VERSION 5.8 ;
BUSBITCHARS "[]" ;
DIVIDERCHAR "/" ;
UNITS
    DATABASE MICRONS 1000 ;
END UNITS

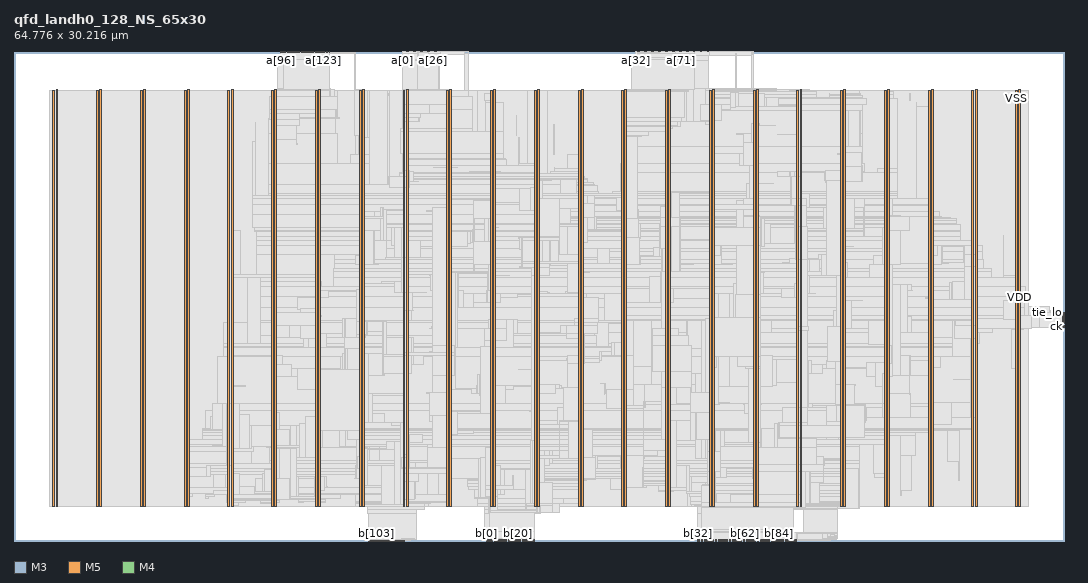
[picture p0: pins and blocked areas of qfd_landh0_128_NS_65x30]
MACRO qfd_landh0_128_NS_65x30
  FOREIGN qfd_landh0_128_NS_65x30 0 0 ;
  CLASS BLOCK ;
  SIZE 64.776 BY 30.216 ;
  PIN a[0]
    DIRECTION INPUT ;
    USE SIGNAL ;
    PORT
      LAYER M3 ;
        RECT  23.94 30.179 23.958 30.216 ;
    END
  END a[0]
  PIN a[100]
    DIRECTION INPUT ;
    USE SIGNAL ;
    PORT
      LAYER M5 ;
        RECT  16.848 30.132 16.872 30.216 ;
    END
  END a[100]
  PIN a[101]
    DIRECTION INPUT ;
    USE SIGNAL ;
    PORT
      LAYER M5 ;
        RECT  16.944 30.132 16.968 30.216 ;
    END
  END a[101]
  PIN a[102]
    DIRECTION INPUT ;
    USE SIGNAL ;
    PORT
      LAYER M5 ;
        RECT  17.04 30.132 17.064 30.216 ;
    END
  END a[102]
  PIN a[103]
    DIRECTION INPUT ;
    USE SIGNAL ;
    PORT
      LAYER M5 ;
        RECT  17.136 30.132 17.16 30.216 ;
    END
  END a[103]
  PIN a[104]
    DIRECTION INPUT ;
    USE SIGNAL ;
    PORT
      LAYER M5 ;
        RECT  17.232 30.132 17.256 30.216 ;
    END
  END a[104]
  PIN a[105]
    DIRECTION INPUT ;
    USE SIGNAL ;
    PORT
      LAYER M5 ;
        RECT  17.328 30.132 17.352 30.216 ;
    END
  END a[105]
  PIN a[106]
    DIRECTION INPUT ;
    USE SIGNAL ;
    PORT
      LAYER M5 ;
        RECT  17.424 30.132 17.448 30.216 ;
    END
  END a[106]
  PIN a[107]
    DIRECTION INPUT ;
    USE SIGNAL ;
    PORT
      LAYER M5 ;
        RECT  17.52 30.132 17.544 30.216 ;
    END
  END a[107]
  PIN a[108]
    DIRECTION INPUT ;
    USE SIGNAL ;
    PORT
      LAYER M5 ;
        RECT  17.616 30.132 17.64 30.216 ;
    END
  END a[108]
  PIN a[109]
    DIRECTION INPUT ;
    USE SIGNAL ;
    PORT
      LAYER M5 ;
        RECT  17.712 30.132 17.736 30.216 ;
    END
  END a[109]
  PIN a[10]
    DIRECTION INPUT ;
    USE SIGNAL ;
    PORT
      LAYER M3 ;
        RECT  24.66 30.179 24.678 30.216 ;
    END
  END a[10]
  PIN a[110]
    DIRECTION INPUT ;
    USE SIGNAL ;
    PORT
      LAYER M5 ;
        RECT  17.808 30.132 17.832 30.216 ;
    END
  END a[110]
  PIN a[111]
    DIRECTION INPUT ;
    USE SIGNAL ;
    PORT
      LAYER M5 ;
        RECT  17.904 30.132 17.928 30.216 ;
    END
  END a[111]
  PIN a[112]
    DIRECTION INPUT ;
    USE SIGNAL ;
    PORT
      LAYER M5 ;
        RECT  18 30.132 18.024 30.216 ;
    END
  END a[112]
  PIN a[113]
    DIRECTION INPUT ;
    USE SIGNAL ;
    PORT
      LAYER M5 ;
        RECT  18.096 30.132 18.12 30.216 ;
    END
  END a[113]
  PIN a[114]
    DIRECTION INPUT ;
    USE SIGNAL ;
    PORT
      LAYER M5 ;
        RECT  18.192 30.132 18.216 30.216 ;
    END
  END a[114]
  PIN a[115]
    DIRECTION INPUT ;
    USE SIGNAL ;
    PORT
      LAYER M5 ;
        RECT  18.288 30.132 18.312 30.216 ;
    END
  END a[115]
  PIN a[116]
    DIRECTION INPUT ;
    USE SIGNAL ;
    PORT
      LAYER M5 ;
        RECT  18.384 30.132 18.408 30.216 ;
    END
  END a[116]
  PIN a[117]
    DIRECTION INPUT ;
    USE SIGNAL ;
    PORT
      LAYER M5 ;
        RECT  18.48 30.132 18.504 30.216 ;
    END
  END a[117]
  PIN a[118]
    DIRECTION INPUT ;
    USE SIGNAL ;
    PORT
      LAYER M5 ;
        RECT  18.576 30.132 18.6 30.216 ;
    END
  END a[118]
  PIN a[119]
    DIRECTION INPUT ;
    USE SIGNAL ;
    PORT
      LAYER M5 ;
        RECT  18.672 30.132 18.696 30.216 ;
    END
  END a[119]
  PIN a[11]
    DIRECTION INPUT ;
    USE SIGNAL ;
    PORT
      LAYER M3 ;
        RECT  24.732 30.179 24.75 30.216 ;
    END
  END a[11]
  PIN a[120]
    DIRECTION INPUT ;
    USE SIGNAL ;
    PORT
      LAYER M5 ;
        RECT  18.768 30.132 18.792 30.216 ;
    END
  END a[120]
  PIN a[121]
    DIRECTION INPUT ;
    USE SIGNAL ;
    PORT
      LAYER M5 ;
        RECT  18.864 30.132 18.888 30.216 ;
    END
  END a[121]
  PIN a[122]
    DIRECTION INPUT ;
    USE SIGNAL ;
    PORT
      LAYER M5 ;
        RECT  18.96 30.132 18.984 30.216 ;
    END
  END a[122]
  PIN a[123]
    DIRECTION INPUT ;
    USE SIGNAL ;
    PORT
      LAYER M5 ;
        RECT  19.056 30.132 19.08 30.216 ;
    END
  END a[123]
  PIN a[124]
    DIRECTION INPUT ;
    USE SIGNAL ;
    PORT
      LAYER M5 ;
        RECT  19.152 30.132 19.176 30.216 ;
    END
  END a[124]
  PIN a[125]
    DIRECTION INPUT ;
    USE SIGNAL ;
    PORT
      LAYER M5 ;
        RECT  19.248 30.132 19.272 30.216 ;
    END
  END a[125]
  PIN a[126]
    DIRECTION INPUT ;
    USE SIGNAL ;
    PORT
      LAYER M5 ;
        RECT  19.344 30.132 19.368 30.216 ;
    END
  END a[126]
  PIN a[127]
    DIRECTION INPUT ;
    USE SIGNAL ;
    PORT
      LAYER M5 ;
        RECT  19.44 30.132 19.464 30.216 ;
    END
  END a[127]
  PIN a[12]
    DIRECTION INPUT ;
    USE SIGNAL ;
    PORT
      LAYER M3 ;
        RECT  24.804 30.179 24.822 30.216 ;
    END
  END a[12]
  PIN a[13]
    DIRECTION INPUT ;
    USE SIGNAL ;
    PORT
      LAYER M3 ;
        RECT  24.876 30.179 24.894 30.216 ;
    END
  END a[13]
  PIN a[14]
    DIRECTION INPUT ;
    USE SIGNAL ;
    PORT
      LAYER M3 ;
        RECT  24.948 30.179 24.966 30.216 ;
    END
  END a[14]
  PIN a[15]
    DIRECTION INPUT ;
    USE SIGNAL ;
    PORT
      LAYER M3 ;
        RECT  25.02 30.179 25.038 30.216 ;
    END
  END a[15]
  PIN a[16]
    DIRECTION INPUT ;
    USE SIGNAL ;
    PORT
      LAYER M3 ;
        RECT  25.092 30.179 25.11 30.216 ;
    END
  END a[16]
  PIN a[17]
    DIRECTION INPUT ;
    USE SIGNAL ;
    PORT
      LAYER M3 ;
        RECT  25.164 30.179 25.182 30.216 ;
    END
  END a[17]
  PIN a[18]
    DIRECTION INPUT ;
    USE SIGNAL ;
    PORT
      LAYER M3 ;
        RECT  25.236 30.179 25.254 30.216 ;
    END
  END a[18]
  PIN a[19]
    DIRECTION INPUT ;
    USE SIGNAL ;
    PORT
      LAYER M3 ;
        RECT  25.308 30.179 25.326 30.216 ;
    END
  END a[19]
  PIN a[1]
    DIRECTION INPUT ;
    USE SIGNAL ;
    PORT
      LAYER M3 ;
        RECT  24.012 30.179 24.03 30.216 ;
    END
  END a[1]
  PIN a[20]
    DIRECTION INPUT ;
    USE SIGNAL ;
    PORT
      LAYER M3 ;
        RECT  25.38 30.179 25.398 30.216 ;
    END
  END a[20]
  PIN a[21]
    DIRECTION INPUT ;
    USE SIGNAL ;
    PORT
      LAYER M3 ;
        RECT  25.452 30.179 25.47 30.216 ;
    END
  END a[21]
  PIN a[22]
    DIRECTION INPUT ;
    USE SIGNAL ;
    PORT
      LAYER M3 ;
        RECT  25.524 30.179 25.542 30.216 ;
    END
  END a[22]
  PIN a[23]
    DIRECTION INPUT ;
    USE SIGNAL ;
    PORT
      LAYER M3 ;
        RECT  25.596 30.179 25.614 30.216 ;
    END
  END a[23]
  PIN a[24]
    DIRECTION INPUT ;
    USE SIGNAL ;
    PORT
      LAYER M3 ;
        RECT  25.668 30.179 25.686 30.216 ;
    END
  END a[24]
  PIN a[25]
    DIRECTION INPUT ;
    USE SIGNAL ;
    PORT
      LAYER M3 ;
        RECT  25.74 30.179 25.758 30.216 ;
    END
  END a[25]
  PIN a[26]
    DIRECTION INPUT ;
    USE SIGNAL ;
    PORT
      LAYER M3 ;
        RECT  25.812 30.179 25.83 30.216 ;
    END
  END a[26]
  PIN a[27]
    DIRECTION INPUT ;
    USE SIGNAL ;
    PORT
      LAYER M3 ;
        RECT  25.884 30.179 25.902 30.216 ;
    END
  END a[27]
  PIN a[28]
    DIRECTION INPUT ;
    USE SIGNAL ;
    PORT
      LAYER M3 ;
        RECT  25.956 30.179 25.974 30.216 ;
    END
  END a[28]
  PIN a[29]
    DIRECTION INPUT ;
    USE SIGNAL ;
    PORT
      LAYER M3 ;
        RECT  26.028 30.179 26.046 30.216 ;
    END
  END a[29]
  PIN a[2]
    DIRECTION INPUT ;
    USE SIGNAL ;
    PORT
      LAYER M3 ;
        RECT  24.084 30.179 24.102 30.216 ;
    END
  END a[2]
  PIN a[30]
    DIRECTION INPUT ;
    USE SIGNAL ;
    PORT
      LAYER M3 ;
        RECT  26.1 30.179 26.118 30.216 ;
    END
  END a[30]
  PIN a[31]
    DIRECTION INPUT ;
    USE SIGNAL ;
    PORT
      LAYER M3 ;
        RECT  26.172 30.179 26.19 30.216 ;
    END
  END a[31]
  PIN a[32]
    DIRECTION INPUT ;
    USE SIGNAL ;
    PORT
      LAYER M3 ;
        RECT  38.34 30.179 38.358 30.216 ;
    END
  END a[32]
  PIN a[33]
    DIRECTION INPUT ;
    USE SIGNAL ;
    PORT
      LAYER M3 ;
        RECT  38.412 30.179 38.43 30.216 ;
    END
  END a[33]
  PIN a[34]
    DIRECTION INPUT ;
    USE SIGNAL ;
    PORT
      LAYER M3 ;
        RECT  38.484 30.179 38.502 30.216 ;
    END
  END a[34]
  PIN a[35]
    DIRECTION INPUT ;
    USE SIGNAL ;
    PORT
      LAYER M3 ;
        RECT  38.556 30.179 38.574 30.216 ;
    END
  END a[35]
  PIN a[36]
    DIRECTION INPUT ;
    USE SIGNAL ;
    PORT
      LAYER M3 ;
        RECT  38.628 30.179 38.646 30.216 ;
    END
  END a[36]
  PIN a[37]
    DIRECTION INPUT ;
    USE SIGNAL ;
    PORT
      LAYER M3 ;
        RECT  38.7 30.179 38.718 30.216 ;
    END
  END a[37]
  PIN a[38]
    DIRECTION INPUT ;
    USE SIGNAL ;
    PORT
      LAYER M3 ;
        RECT  38.772 30.179 38.79 30.216 ;
    END
  END a[38]
  PIN a[39]
    DIRECTION INPUT ;
    USE SIGNAL ;
    PORT
      LAYER M3 ;
        RECT  38.844 30.179 38.862 30.216 ;
    END
  END a[39]
  PIN a[3]
    DIRECTION INPUT ;
    USE SIGNAL ;
    PORT
      LAYER M3 ;
        RECT  24.156 30.179 24.174 30.216 ;
    END
  END a[3]
  PIN a[40]
    DIRECTION INPUT ;
    USE SIGNAL ;
    PORT
      LAYER M3 ;
        RECT  38.916 30.179 38.934 30.216 ;
    END
  END a[40]
  PIN a[41]
    DIRECTION INPUT ;
    USE SIGNAL ;
    PORT
      LAYER M3 ;
        RECT  38.988 30.179 39.006 30.216 ;
    END
  END a[41]
  PIN a[42]
    DIRECTION INPUT ;
    USE SIGNAL ;
    PORT
      LAYER M3 ;
        RECT  39.06 30.179 39.078 30.216 ;
    END
  END a[42]
  PIN a[43]
    DIRECTION INPUT ;
    USE SIGNAL ;
    PORT
      LAYER M3 ;
        RECT  39.132 30.179 39.15 30.216 ;
    END
  END a[43]
  PIN a[44]
    DIRECTION INPUT ;
    USE SIGNAL ;
    PORT
      LAYER M3 ;
        RECT  39.204 30.179 39.222 30.216 ;
    END
  END a[44]
  PIN a[45]
    DIRECTION INPUT ;
    USE SIGNAL ;
    PORT
      LAYER M3 ;
        RECT  39.276 30.179 39.294 30.216 ;
    END
  END a[45]
  PIN a[46]
    DIRECTION INPUT ;
    USE SIGNAL ;
    PORT
      LAYER M3 ;
        RECT  39.348 30.179 39.366 30.216 ;
    END
  END a[46]
  PIN a[47]
    DIRECTION INPUT ;
    USE SIGNAL ;
    PORT
      LAYER M3 ;
        RECT  39.42 30.179 39.438 30.216 ;
    END
  END a[47]
  PIN a[48]
    DIRECTION INPUT ;
    USE SIGNAL ;
    PORT
      LAYER M3 ;
        RECT  39.492 30.179 39.51 30.216 ;
    END
  END a[48]
  PIN a[49]
    DIRECTION INPUT ;
    USE SIGNAL ;
    PORT
      LAYER M3 ;
        RECT  39.564 30.179 39.582 30.216 ;
    END
  END a[49]
  PIN a[4]
    DIRECTION INPUT ;
    USE SIGNAL ;
    PORT
      LAYER M3 ;
        RECT  24.228 30.179 24.246 30.216 ;
    END
  END a[4]
  PIN a[50]
    DIRECTION INPUT ;
    USE SIGNAL ;
    PORT
      LAYER M3 ;
        RECT  39.636 30.179 39.654 30.216 ;
    END
  END a[50]
  PIN a[51]
    DIRECTION INPUT ;
    USE SIGNAL ;
    PORT
      LAYER M3 ;
        RECT  39.708 30.179 39.726 30.216 ;
    END
  END a[51]
  PIN a[52]
    DIRECTION INPUT ;
    USE SIGNAL ;
    PORT
      LAYER M3 ;
        RECT  39.78 30.179 39.798 30.216 ;
    END
  END a[52]
  PIN a[53]
    DIRECTION INPUT ;
    USE SIGNAL ;
    PORT
      LAYER M3 ;
        RECT  39.852 30.179 39.87 30.216 ;
    END
  END a[53]
  PIN a[54]
    DIRECTION INPUT ;
    USE SIGNAL ;
    PORT
      LAYER M3 ;
        RECT  39.924 30.179 39.942 30.216 ;
    END
  END a[54]
  PIN a[55]
    DIRECTION INPUT ;
    USE SIGNAL ;
    PORT
      LAYER M3 ;
        RECT  39.996 30.179 40.014 30.216 ;
    END
  END a[55]
  PIN a[56]
    DIRECTION INPUT ;
    USE SIGNAL ;
    PORT
      LAYER M3 ;
        RECT  40.068 30.179 40.086 30.216 ;
    END
  END a[56]
  PIN a[57]
    DIRECTION INPUT ;
    USE SIGNAL ;
    PORT
      LAYER M3 ;
        RECT  40.14 30.179 40.158 30.216 ;
    END
  END a[57]
  PIN a[58]
    DIRECTION INPUT ;
    USE SIGNAL ;
    PORT
      LAYER M3 ;
        RECT  40.212 30.179 40.23 30.216 ;
    END
  END a[58]
  PIN a[59]
    DIRECTION INPUT ;
    USE SIGNAL ;
    PORT
      LAYER M3 ;
        RECT  40.284 30.179 40.302 30.216 ;
    END
  END a[59]
  PIN a[5]
    DIRECTION INPUT ;
    USE SIGNAL ;
    PORT
      LAYER M3 ;
        RECT  24.3 30.179 24.318 30.216 ;
    END
  END a[5]
  PIN a[60]
    DIRECTION INPUT ;
    USE SIGNAL ;
    PORT
      LAYER M3 ;
        RECT  40.356 30.179 40.374 30.216 ;
    END
  END a[60]
  PIN a[61]
    DIRECTION INPUT ;
    USE SIGNAL ;
    PORT
      LAYER M3 ;
        RECT  40.428 30.179 40.446 30.216 ;
    END
  END a[61]
  PIN a[62]
    DIRECTION INPUT ;
    USE SIGNAL ;
    PORT
      LAYER M3 ;
        RECT  40.5 30.179 40.518 30.216 ;
    END
  END a[62]
  PIN a[63]
    DIRECTION INPUT ;
    USE SIGNAL ;
    PORT
      LAYER M3 ;
        RECT  40.572 30.179 40.59 30.216 ;
    END
  END a[63]
  PIN a[64]
    DIRECTION INPUT ;
    USE SIGNAL ;
    PORT
      LAYER M3 ;
        RECT  40.644 30.179 40.662 30.216 ;
    END
  END a[64]
  PIN a[65]
    DIRECTION INPUT ;
    USE SIGNAL ;
    PORT
      LAYER M3 ;
        RECT  40.716 30.179 40.734 30.216 ;
    END
  END a[65]
  PIN a[66]
    DIRECTION INPUT ;
    USE SIGNAL ;
    PORT
      LAYER M3 ;
        RECT  40.788 30.179 40.806 30.216 ;
    END
  END a[66]
  PIN a[67]
    DIRECTION INPUT ;
    USE SIGNAL ;
    PORT
      LAYER M3 ;
        RECT  40.86 30.179 40.878 30.216 ;
    END
  END a[67]
  PIN a[68]
    DIRECTION INPUT ;
    USE SIGNAL ;
    PORT
      LAYER M3 ;
        RECT  40.932 30.179 40.95 30.216 ;
    END
  END a[68]
  PIN a[69]
    DIRECTION INPUT ;
    USE SIGNAL ;
    PORT
      LAYER M3 ;
        RECT  41.004 30.179 41.022 30.216 ;
    END
  END a[69]
  PIN a[6]
    DIRECTION INPUT ;
    USE SIGNAL ;
    PORT
      LAYER M3 ;
        RECT  24.372 30.179 24.39 30.216 ;
    END
  END a[6]
  PIN a[70]
    DIRECTION INPUT ;
    USE SIGNAL ;
    PORT
      LAYER M3 ;
        RECT  41.076 30.179 41.094 30.216 ;
    END
  END a[70]
  PIN a[71]
    DIRECTION INPUT ;
    USE SIGNAL ;
    PORT
      LAYER M3 ;
        RECT  41.148 30.179 41.166 30.216 ;
    END
  END a[71]
  PIN a[72]
    DIRECTION INPUT ;
    USE SIGNAL ;
    PORT
      LAYER M3 ;
        RECT  41.22 30.179 41.238 30.216 ;
    END
  END a[72]
  PIN a[73]
    DIRECTION INPUT ;
    USE SIGNAL ;
    PORT
      LAYER M3 ;
        RECT  41.292 30.179 41.31 30.216 ;
    END
  END a[73]
  PIN a[74]
    DIRECTION INPUT ;
    USE SIGNAL ;
    PORT
      LAYER M3 ;
        RECT  41.364 30.179 41.382 30.216 ;
    END
  END a[74]
  PIN a[75]
    DIRECTION INPUT ;
    USE SIGNAL ;
    PORT
      LAYER M3 ;
        RECT  41.436 30.179 41.454 30.216 ;
    END
  END a[75]
  PIN a[76]
    DIRECTION INPUT ;
    USE SIGNAL ;
    PORT
      LAYER M3 ;
        RECT  41.508 30.179 41.526 30.216 ;
    END
  END a[76]
  PIN a[77]
    DIRECTION INPUT ;
    USE SIGNAL ;
    PORT
      LAYER M3 ;
        RECT  41.58 30.179 41.598 30.216 ;
    END
  END a[77]
  PIN a[78]
    DIRECTION INPUT ;
    USE SIGNAL ;
    PORT
      LAYER M3 ;
        RECT  41.652 30.179 41.67 30.216 ;
    END
  END a[78]
  PIN a[79]
    DIRECTION INPUT ;
    USE SIGNAL ;
    PORT
      LAYER M3 ;
        RECT  41.724 30.179 41.742 30.216 ;
    END
  END a[79]
  PIN a[7]
    DIRECTION INPUT ;
    USE SIGNAL ;
    PORT
      LAYER M3 ;
        RECT  24.444 30.179 24.462 30.216 ;
    END
  END a[7]
  PIN a[80]
    DIRECTION INPUT ;
    USE SIGNAL ;
    PORT
      LAYER M3 ;
        RECT  41.796 30.179 41.814 30.216 ;
    END
  END a[80]
  PIN a[81]
    DIRECTION INPUT ;
    USE SIGNAL ;
    PORT
      LAYER M3 ;
        RECT  41.868 30.179 41.886 30.216 ;
    END
  END a[81]
  PIN a[82]
    DIRECTION INPUT ;
    USE SIGNAL ;
    PORT
      LAYER M3 ;
        RECT  41.94 30.179 41.958 30.216 ;
    END
  END a[82]
  PIN a[83]
    DIRECTION INPUT ;
    USE SIGNAL ;
    PORT
      LAYER M3 ;
        RECT  42.012 30.179 42.03 30.216 ;
    END
  END a[83]
  PIN a[84]
    DIRECTION INPUT ;
    USE SIGNAL ;
    PORT
      LAYER M3 ;
        RECT  42.084 30.179 42.102 30.216 ;
    END
  END a[84]
  PIN a[85]
    DIRECTION INPUT ;
    USE SIGNAL ;
    PORT
      LAYER M3 ;
        RECT  42.156 30.179 42.174 30.216 ;
    END
  END a[85]
  PIN a[86]
    DIRECTION INPUT ;
    USE SIGNAL ;
    PORT
      LAYER M3 ;
        RECT  42.228 30.179 42.246 30.216 ;
    END
  END a[86]
  PIN a[87]
    DIRECTION INPUT ;
    USE SIGNAL ;
    PORT
      LAYER M3 ;
        RECT  42.3 30.179 42.318 30.216 ;
    END
  END a[87]
  PIN a[88]
    DIRECTION INPUT ;
    USE SIGNAL ;
    PORT
      LAYER M3 ;
        RECT  42.372 30.179 42.39 30.216 ;
    END
  END a[88]
  PIN a[89]
    DIRECTION INPUT ;
    USE SIGNAL ;
    PORT
      LAYER M3 ;
        RECT  42.444 30.179 42.462 30.216 ;
    END
  END a[89]
  PIN a[8]
    DIRECTION INPUT ;
    USE SIGNAL ;
    PORT
      LAYER M3 ;
        RECT  24.516 30.179 24.534 30.216 ;
    END
  END a[8]
  PIN a[90]
    DIRECTION INPUT ;
    USE SIGNAL ;
    PORT
      LAYER M3 ;
        RECT  42.516 30.179 42.534 30.216 ;
    END
  END a[90]
  PIN a[91]
    DIRECTION INPUT ;
    USE SIGNAL ;
    PORT
      LAYER M3 ;
        RECT  42.588 30.179 42.606 30.216 ;
    END
  END a[91]
  PIN a[92]
    DIRECTION INPUT ;
    USE SIGNAL ;
    PORT
      LAYER M3 ;
        RECT  42.66 30.179 42.678 30.216 ;
    END
  END a[92]
  PIN a[93]
    DIRECTION INPUT ;
    USE SIGNAL ;
    PORT
      LAYER M3 ;
        RECT  42.732 30.179 42.75 30.216 ;
    END
  END a[93]
  PIN a[94]
    DIRECTION INPUT ;
    USE SIGNAL ;
    PORT
      LAYER M3 ;
        RECT  42.804 30.179 42.822 30.216 ;
    END
  END a[94]
  PIN a[95]
    DIRECTION INPUT ;
    USE SIGNAL ;
    PORT
      LAYER M3 ;
        RECT  42.876 30.179 42.894 30.216 ;
    END
  END a[95]
  PIN a[96]
    DIRECTION INPUT ;
    USE SIGNAL ;
    PORT
      LAYER M5 ;
        RECT  16.464 30.132 16.488 30.216 ;
    END
  END a[96]
  PIN a[97]
    DIRECTION INPUT ;
    USE SIGNAL ;
    PORT
      LAYER M5 ;
        RECT  16.56 30.132 16.584 30.216 ;
    END
  END a[97]
  PIN a[98]
    DIRECTION INPUT ;
    USE SIGNAL ;
    PORT
      LAYER M5 ;
        RECT  16.656 30.132 16.68 30.216 ;
    END
  END a[98]
  PIN a[99]
    DIRECTION INPUT ;
    USE SIGNAL ;
    PORT
      LAYER M5 ;
        RECT  16.752 30.132 16.776 30.216 ;
    END
  END a[99]
  PIN a[9]
    DIRECTION INPUT ;
    USE SIGNAL ;
    PORT
      LAYER M3 ;
        RECT  24.588 30.179 24.606 30.216 ;
    END
  END a[9]
  PIN b[0]
    DIRECTION OUTPUT ;
    USE SIGNAL ;
    PORT
      LAYER M5 ;
        RECT  29.136 0 29.16 0.084 ;
    END
  END b[0]
  PIN b[100]
    DIRECTION OUTPUT ;
    USE SIGNAL ;
    PORT
      LAYER M3 ;
        RECT  22.14 0 22.158 0.037 ;
    END
  END b[100]
  PIN b[101]
    DIRECTION OUTPUT ;
    USE SIGNAL ;
    PORT
      LAYER M3 ;
        RECT  22.212 0 22.23 0.037 ;
    END
  END b[101]
  PIN b[102]
    DIRECTION OUTPUT ;
    USE SIGNAL ;
    PORT
      LAYER M3 ;
        RECT  22.284 0 22.302 0.037 ;
    END
  END b[102]
  PIN b[103]
    DIRECTION OUTPUT ;
    USE SIGNAL ;
    PORT
      LAYER M3 ;
        RECT  22.356 0 22.374 0.037 ;
    END
  END b[103]
  PIN b[104]
    DIRECTION OUTPUT ;
    USE SIGNAL ;
    PORT
      LAYER M3 ;
        RECT  22.428 0 22.446 0.037 ;
    END
  END b[104]
  PIN b[105]
    DIRECTION OUTPUT ;
    USE SIGNAL ;
    PORT
      LAYER M3 ;
        RECT  22.5 0 22.518 0.037 ;
    END
  END b[105]
  PIN b[106]
    DIRECTION OUTPUT ;
    USE SIGNAL ;
    PORT
      LAYER M3 ;
        RECT  22.572 0 22.59 0.037 ;
    END
  END b[106]
  PIN b[107]
    DIRECTION OUTPUT ;
    USE SIGNAL ;
    PORT
      LAYER M3 ;
        RECT  22.644 0 22.662 0.037 ;
    END
  END b[107]
  PIN b[108]
    DIRECTION OUTPUT ;
    USE SIGNAL ;
    PORT
      LAYER M3 ;
        RECT  22.716 0 22.734 0.037 ;
    END
  END b[108]
  PIN b[109]
    DIRECTION OUTPUT ;
    USE SIGNAL ;
    PORT
      LAYER M3 ;
        RECT  22.788 0 22.806 0.037 ;
    END
  END b[109]
  PIN b[10]
    DIRECTION OUTPUT ;
    USE SIGNAL ;
    PORT
      LAYER M5 ;
        RECT  30.096 0 30.12 0.084 ;
    END
  END b[10]
  PIN b[110]
    DIRECTION OUTPUT ;
    USE SIGNAL ;
    PORT
      LAYER M3 ;
        RECT  22.86 0 22.878 0.037 ;
    END
  END b[110]
  PIN b[111]
    DIRECTION OUTPUT ;
    USE SIGNAL ;
    PORT
      LAYER M3 ;
        RECT  22.932 0 22.95 0.037 ;
    END
  END b[111]
  PIN b[112]
    DIRECTION OUTPUT ;
    USE SIGNAL ;
    PORT
      LAYER M3 ;
        RECT  23.004 0 23.022 0.037 ;
    END
  END b[112]
  PIN b[113]
    DIRECTION OUTPUT ;
    USE SIGNAL ;
    PORT
      LAYER M3 ;
        RECT  23.076 0 23.094 0.037 ;
    END
  END b[113]
  PIN b[114]
    DIRECTION OUTPUT ;
    USE SIGNAL ;
    PORT
      LAYER M3 ;
        RECT  23.148 0 23.166 0.037 ;
    END
  END b[114]
  PIN b[115]
    DIRECTION OUTPUT ;
    USE SIGNAL ;
    PORT
      LAYER M3 ;
        RECT  23.22 0 23.238 0.037 ;
    END
  END b[115]
  PIN b[116]
    DIRECTION OUTPUT ;
    USE SIGNAL ;
    PORT
      LAYER M3 ;
        RECT  23.292 0 23.31 0.037 ;
    END
  END b[116]
  PIN b[117]
    DIRECTION OUTPUT ;
    USE SIGNAL ;
    PORT
      LAYER M3 ;
        RECT  23.364 0 23.382 0.037 ;
    END
  END b[117]
  PIN b[118]
    DIRECTION OUTPUT ;
    USE SIGNAL ;
    PORT
      LAYER M3 ;
        RECT  23.436 0 23.454 0.037 ;
    END
  END b[118]
  PIN b[119]
    DIRECTION OUTPUT ;
    USE SIGNAL ;
    PORT
      LAYER M3 ;
        RECT  23.508 0 23.526 0.037 ;
    END
  END b[119]
  PIN b[11]
    DIRECTION OUTPUT ;
    USE SIGNAL ;
    PORT
      LAYER M5 ;
        RECT  30.192 0 30.216 0.084 ;
    END
  END b[11]
  PIN b[120]
    DIRECTION OUTPUT ;
    USE SIGNAL ;
    PORT
      LAYER M3 ;
        RECT  23.58 0 23.598 0.037 ;
    END
  END b[120]
  PIN b[121]
    DIRECTION OUTPUT ;
    USE SIGNAL ;
    PORT
      LAYER M3 ;
        RECT  23.652 0 23.67 0.037 ;
    END
  END b[121]
  PIN b[122]
    DIRECTION OUTPUT ;
    USE SIGNAL ;
    PORT
      LAYER M3 ;
        RECT  23.724 0 23.742 0.037 ;
    END
  END b[122]
  PIN b[123]
    DIRECTION OUTPUT ;
    USE SIGNAL ;
    PORT
      LAYER M3 ;
        RECT  23.796 0 23.814 0.037 ;
    END
  END b[123]
  PIN b[124]
    DIRECTION OUTPUT ;
    USE SIGNAL ;
    PORT
      LAYER M3 ;
        RECT  23.868 0 23.886 0.037 ;
    END
  END b[124]
  PIN b[125]
    DIRECTION OUTPUT ;
    USE SIGNAL ;
    PORT
      LAYER M3 ;
        RECT  23.94 0 23.958 0.037 ;
    END
  END b[125]
  PIN b[126]
    DIRECTION OUTPUT ;
    USE SIGNAL ;
    PORT
      LAYER M3 ;
        RECT  24.012 0 24.03 0.037 ;
    END
  END b[126]
  PIN b[127]
    DIRECTION OUTPUT ;
    USE SIGNAL ;
    PORT
      LAYER M3 ;
        RECT  24.084 0 24.102 0.037 ;
    END
  END b[127]
  PIN b[12]
    DIRECTION OUTPUT ;
    USE SIGNAL ;
    PORT
      LAYER M5 ;
        RECT  30.288 0 30.312 0.084 ;
    END
  END b[12]
  PIN b[13]
    DIRECTION OUTPUT ;
    USE SIGNAL ;
    PORT
      LAYER M5 ;
        RECT  30.384 0 30.408 0.084 ;
    END
  END b[13]
  PIN b[14]
    DIRECTION OUTPUT ;
    USE SIGNAL ;
    PORT
      LAYER M5 ;
        RECT  30.48 0 30.504 0.084 ;
    END
  END b[14]
  PIN b[15]
    DIRECTION OUTPUT ;
    USE SIGNAL ;
    PORT
      LAYER M5 ;
        RECT  30.576 0 30.6 0.084 ;
    END
  END b[15]
  PIN b[16]
    DIRECTION OUTPUT ;
    USE SIGNAL ;
    PORT
      LAYER M5 ;
        RECT  30.672 0 30.696 0.084 ;
    END
  END b[16]
  PIN b[17]
    DIRECTION OUTPUT ;
    USE SIGNAL ;
    PORT
      LAYER M5 ;
        RECT  30.768 0 30.792 0.084 ;
    END
  END b[17]
  PIN b[18]
    DIRECTION OUTPUT ;
    USE SIGNAL ;
    PORT
      LAYER M5 ;
        RECT  30.864 0 30.888 0.084 ;
    END
  END b[18]
  PIN b[19]
    DIRECTION OUTPUT ;
    USE SIGNAL ;
    PORT
      LAYER M5 ;
        RECT  30.96 0 30.984 0.084 ;
    END
  END b[19]
  PIN b[1]
    DIRECTION OUTPUT ;
    USE SIGNAL ;
    PORT
      LAYER M5 ;
        RECT  29.232 0 29.256 0.084 ;
    END
  END b[1]
  PIN b[20]
    DIRECTION OUTPUT ;
    USE SIGNAL ;
    PORT
      LAYER M5 ;
        RECT  31.056 0 31.08 0.084 ;
    END
  END b[20]
  PIN b[21]
    DIRECTION OUTPUT ;
    USE SIGNAL ;
    PORT
      LAYER M5 ;
        RECT  31.152 0 31.176 0.084 ;
    END
  END b[21]
  PIN b[22]
    DIRECTION OUTPUT ;
    USE SIGNAL ;
    PORT
      LAYER M5 ;
        RECT  31.248 0 31.272 0.084 ;
    END
  END b[22]
  PIN b[23]
    DIRECTION OUTPUT ;
    USE SIGNAL ;
    PORT
      LAYER M5 ;
        RECT  31.344 0 31.368 0.084 ;
    END
  END b[23]
  PIN b[24]
    DIRECTION OUTPUT ;
    USE SIGNAL ;
    PORT
      LAYER M5 ;
        RECT  31.44 0 31.464 0.084 ;
    END
  END b[24]
  PIN b[25]
    DIRECTION OUTPUT ;
    USE SIGNAL ;
    PORT
      LAYER M5 ;
        RECT  31.536 0 31.56 0.084 ;
    END
  END b[25]
  PIN b[26]
    DIRECTION OUTPUT ;
    USE SIGNAL ;
    PORT
      LAYER M5 ;
        RECT  31.632 0 31.656 0.084 ;
    END
  END b[26]
  PIN b[27]
    DIRECTION OUTPUT ;
    USE SIGNAL ;
    PORT
      LAYER M5 ;
        RECT  31.728 0 31.752 0.084 ;
    END
  END b[27]
  PIN b[28]
    DIRECTION OUTPUT ;
    USE SIGNAL ;
    PORT
      LAYER M5 ;
        RECT  31.824 0 31.848 0.084 ;
    END
  END b[28]
  PIN b[29]
    DIRECTION OUTPUT ;
    USE SIGNAL ;
    PORT
      LAYER M5 ;
        RECT  31.92 0 31.944 0.084 ;
    END
  END b[29]
  PIN b[2]
    DIRECTION OUTPUT ;
    USE SIGNAL ;
    PORT
      LAYER M5 ;
        RECT  29.328 0 29.352 0.084 ;
    END
  END b[2]
  PIN b[30]
    DIRECTION OUTPUT ;
    USE SIGNAL ;
    PORT
      LAYER M5 ;
        RECT  32.016 0 32.04 0.084 ;
    END
  END b[30]
  PIN b[31]
    DIRECTION OUTPUT ;
    USE SIGNAL ;
    PORT
      LAYER M5 ;
        RECT  32.112 0 32.136 0.084 ;
    END
  END b[31]
  PIN b[32]
    DIRECTION OUTPUT ;
    USE SIGNAL ;
    PORT
      LAYER M5 ;
        RECT  42.192 0 42.216 0.084 ;
    END
  END b[32]
  PIN b[33]
    DIRECTION OUTPUT ;
    USE SIGNAL ;
    PORT
      LAYER M5 ;
        RECT  42.288 0 42.312 0.084 ;
    END
  END b[33]
  PIN b[34]
    DIRECTION OUTPUT ;
    USE SIGNAL ;
    PORT
      LAYER M5 ;
        RECT  42.384 0 42.408 0.084 ;
    END
  END b[34]
  PIN b[35]
    DIRECTION OUTPUT ;
    USE SIGNAL ;
    PORT
      LAYER M5 ;
        RECT  42.48 0 42.504 0.084 ;
    END
  END b[35]
  PIN b[36]
    DIRECTION OUTPUT ;
    USE SIGNAL ;
    PORT
      LAYER M5 ;
        RECT  42.576 0 42.6 0.084 ;
    END
  END b[36]
  PIN b[37]
    DIRECTION OUTPUT ;
    USE SIGNAL ;
    PORT
      LAYER M5 ;
        RECT  42.672 0 42.696 0.084 ;
    END
  END b[37]
  PIN b[38]
    DIRECTION OUTPUT ;
    USE SIGNAL ;
    PORT
      LAYER M5 ;
        RECT  42.768 0 42.792 0.084 ;
    END
  END b[38]
  PIN b[39]
    DIRECTION OUTPUT ;
    USE SIGNAL ;
    PORT
      LAYER M5 ;
        RECT  42.864 0 42.888 0.084 ;
    END
  END b[39]
  PIN b[3]
    DIRECTION OUTPUT ;
    USE SIGNAL ;
    PORT
      LAYER M5 ;
        RECT  29.424 0 29.448 0.084 ;
    END
  END b[3]
  PIN b[40]
    DIRECTION OUTPUT ;
    USE SIGNAL ;
    PORT
      LAYER M5 ;
        RECT  42.96 0 42.984 0.084 ;
    END
  END b[40]
  PIN b[41]
    DIRECTION OUTPUT ;
    USE SIGNAL ;
    PORT
      LAYER M5 ;
        RECT  43.056 0 43.08 0.084 ;
    END
  END b[41]
  PIN b[42]
    DIRECTION OUTPUT ;
    USE SIGNAL ;
    PORT
      LAYER M5 ;
        RECT  43.152 0 43.176 0.084 ;
    END
  END b[42]
  PIN b[43]
    DIRECTION OUTPUT ;
    USE SIGNAL ;
    PORT
      LAYER M5 ;
        RECT  43.248 0 43.272 0.084 ;
    END
  END b[43]
  PIN b[44]
    DIRECTION OUTPUT ;
    USE SIGNAL ;
    PORT
      LAYER M5 ;
        RECT  43.344 0 43.368 0.084 ;
    END
  END b[44]
  PIN b[45]
    DIRECTION OUTPUT ;
    USE SIGNAL ;
    PORT
      LAYER M5 ;
        RECT  43.44 0 43.464 0.084 ;
    END
  END b[45]
  PIN b[46]
    DIRECTION OUTPUT ;
    USE SIGNAL ;
    PORT
      LAYER M5 ;
        RECT  43.536 0 43.56 0.084 ;
    END
  END b[46]
  PIN b[47]
    DIRECTION OUTPUT ;
    USE SIGNAL ;
    PORT
      LAYER M5 ;
        RECT  43.632 0 43.656 0.084 ;
    END
  END b[47]
  PIN b[48]
    DIRECTION OUTPUT ;
    USE SIGNAL ;
    PORT
      LAYER M5 ;
        RECT  43.728 0 43.752 0.084 ;
    END
  END b[48]
  PIN b[49]
    DIRECTION OUTPUT ;
    USE SIGNAL ;
    PORT
      LAYER M5 ;
        RECT  43.824 0 43.848 0.084 ;
    END
  END b[49]
  PIN b[4]
    DIRECTION OUTPUT ;
    USE SIGNAL ;
    PORT
      LAYER M5 ;
        RECT  29.52 0 29.544 0.084 ;
    END
  END b[4]
  PIN b[50]
    DIRECTION OUTPUT ;
    USE SIGNAL ;
    PORT
      LAYER M5 ;
        RECT  43.92 0 43.944 0.084 ;
    END
  END b[50]
  PIN b[51]
    DIRECTION OUTPUT ;
    USE SIGNAL ;
    PORT
      LAYER M5 ;
        RECT  44.016 0 44.04 0.084 ;
    END
  END b[51]
  PIN b[52]
    DIRECTION OUTPUT ;
    USE SIGNAL ;
    PORT
      LAYER M5 ;
        RECT  44.112 0 44.136 0.084 ;
    END
  END b[52]
  PIN b[53]
    DIRECTION OUTPUT ;
    USE SIGNAL ;
    PORT
      LAYER M5 ;
        RECT  44.208 0 44.232 0.084 ;
    END
  END b[53]
  PIN b[54]
    DIRECTION OUTPUT ;
    USE SIGNAL ;
    PORT
      LAYER M5 ;
        RECT  44.304 0 44.328 0.084 ;
    END
  END b[54]
  PIN b[55]
    DIRECTION OUTPUT ;
    USE SIGNAL ;
    PORT
      LAYER M5 ;
        RECT  44.4 0 44.424 0.084 ;
    END
  END b[55]
  PIN b[56]
    DIRECTION OUTPUT ;
    USE SIGNAL ;
    PORT
      LAYER M5 ;
        RECT  44.496 0 44.52 0.084 ;
    END
  END b[56]
  PIN b[57]
    DIRECTION OUTPUT ;
    USE SIGNAL ;
    PORT
      LAYER M5 ;
        RECT  44.592 0 44.616 0.084 ;
    END
  END b[57]
  PIN b[58]
    DIRECTION OUTPUT ;
    USE SIGNAL ;
    PORT
      LAYER M5 ;
        RECT  44.688 0 44.712 0.084 ;
    END
  END b[58]
  PIN b[59]
    DIRECTION OUTPUT ;
    USE SIGNAL ;
    PORT
      LAYER M5 ;
        RECT  44.784 0 44.808 0.084 ;
    END
  END b[59]
  PIN b[5]
    DIRECTION OUTPUT ;
    USE SIGNAL ;
    PORT
      LAYER M5 ;
        RECT  29.616 0 29.64 0.084 ;
    END
  END b[5]
  PIN b[60]
    DIRECTION OUTPUT ;
    USE SIGNAL ;
    PORT
      LAYER M5 ;
        RECT  44.88 0 44.904 0.084 ;
    END
  END b[60]
  PIN b[61]
    DIRECTION OUTPUT ;
    USE SIGNAL ;
    PORT
      LAYER M5 ;
        RECT  44.976 0 45 0.084 ;
    END
  END b[61]
  PIN b[62]
    DIRECTION OUTPUT ;
    USE SIGNAL ;
    PORT
      LAYER M5 ;
        RECT  45.072 0 45.096 0.084 ;
    END
  END b[62]
  PIN b[63]
    DIRECTION OUTPUT ;
    USE SIGNAL ;
    PORT
      LAYER M5 ;
        RECT  45.168 0 45.192 0.084 ;
    END
  END b[63]
  PIN b[64]
    DIRECTION OUTPUT ;
    USE SIGNAL ;
    PORT
      LAYER M5 ;
        RECT  45.264 0 45.288 0.084 ;
    END
  END b[64]
  PIN b[65]
    DIRECTION OUTPUT ;
    USE SIGNAL ;
    PORT
      LAYER M5 ;
        RECT  45.36 0 45.384 0.084 ;
    END
  END b[65]
  PIN b[66]
    DIRECTION OUTPUT ;
    USE SIGNAL ;
    PORT
      LAYER M5 ;
        RECT  45.456 0 45.48 0.084 ;
    END
  END b[66]
  PIN b[67]
    DIRECTION OUTPUT ;
    USE SIGNAL ;
    PORT
      LAYER M5 ;
        RECT  45.552 0 45.576 0.084 ;
    END
  END b[67]
  PIN b[68]
    DIRECTION OUTPUT ;
    USE SIGNAL ;
    PORT
      LAYER M5 ;
        RECT  45.648 0 45.672 0.084 ;
    END
  END b[68]
  PIN b[69]
    DIRECTION OUTPUT ;
    USE SIGNAL ;
    PORT
      LAYER M5 ;
        RECT  45.744 0 45.768 0.084 ;
    END
  END b[69]
  PIN b[6]
    DIRECTION OUTPUT ;
    USE SIGNAL ;
    PORT
      LAYER M5 ;
        RECT  29.712 0 29.736 0.084 ;
    END
  END b[6]
  PIN b[70]
    DIRECTION OUTPUT ;
    USE SIGNAL ;
    PORT
      LAYER M5 ;
        RECT  45.84 0 45.864 0.084 ;
    END
  END b[70]
  PIN b[71]
    DIRECTION OUTPUT ;
    USE SIGNAL ;
    PORT
      LAYER M5 ;
        RECT  45.936 0 45.96 0.084 ;
    END
  END b[71]
  PIN b[72]
    DIRECTION OUTPUT ;
    USE SIGNAL ;
    PORT
      LAYER M5 ;
        RECT  46.032 0 46.056 0.084 ;
    END
  END b[72]
  PIN b[73]
    DIRECTION OUTPUT ;
    USE SIGNAL ;
    PORT
      LAYER M5 ;
        RECT  46.128 0 46.152 0.084 ;
    END
  END b[73]
  PIN b[74]
    DIRECTION OUTPUT ;
    USE SIGNAL ;
    PORT
      LAYER M5 ;
        RECT  46.224 0 46.248 0.084 ;
    END
  END b[74]
  PIN b[75]
    DIRECTION OUTPUT ;
    USE SIGNAL ;
    PORT
      LAYER M5 ;
        RECT  46.32 0 46.344 0.084 ;
    END
  END b[75]
  PIN b[76]
    DIRECTION OUTPUT ;
    USE SIGNAL ;
    PORT
      LAYER M5 ;
        RECT  46.416 0 46.44 0.084 ;
    END
  END b[76]
  PIN b[77]
    DIRECTION OUTPUT ;
    USE SIGNAL ;
    PORT
      LAYER M5 ;
        RECT  46.512 0 46.536 0.084 ;
    END
  END b[77]
  PIN b[78]
    DIRECTION OUTPUT ;
    USE SIGNAL ;
    PORT
      LAYER M5 ;
        RECT  46.608 0 46.632 0.084 ;
    END
  END b[78]
  PIN b[79]
    DIRECTION OUTPUT ;
    USE SIGNAL ;
    PORT
      LAYER M5 ;
        RECT  46.704 0 46.728 0.084 ;
    END
  END b[79]
  PIN b[7]
    DIRECTION OUTPUT ;
    USE SIGNAL ;
    PORT
      LAYER M5 ;
        RECT  29.808 0 29.832 0.084 ;
    END
  END b[7]
  PIN b[80]
    DIRECTION OUTPUT ;
    USE SIGNAL ;
    PORT
      LAYER M5 ;
        RECT  46.8 0 46.824 0.084 ;
    END
  END b[80]
  PIN b[81]
    DIRECTION OUTPUT ;
    USE SIGNAL ;
    PORT
      LAYER M5 ;
        RECT  46.896 0 46.92 0.084 ;
    END
  END b[81]
  PIN b[82]
    DIRECTION OUTPUT ;
    USE SIGNAL ;
    PORT
      LAYER M5 ;
        RECT  46.992 0 47.016 0.084 ;
    END
  END b[82]
  PIN b[83]
    DIRECTION OUTPUT ;
    USE SIGNAL ;
    PORT
      LAYER M5 ;
        RECT  47.088 0 47.112 0.084 ;
    END
  END b[83]
  PIN b[84]
    DIRECTION OUTPUT ;
    USE SIGNAL ;
    PORT
      LAYER M5 ;
        RECT  47.184 0 47.208 0.084 ;
    END
  END b[84]
  PIN b[85]
    DIRECTION OUTPUT ;
    USE SIGNAL ;
    PORT
      LAYER M5 ;
        RECT  47.28 0 47.304 0.084 ;
    END
  END b[85]
  PIN b[86]
    DIRECTION OUTPUT ;
    USE SIGNAL ;
    PORT
      LAYER M5 ;
        RECT  47.376 0 47.4 0.084 ;
    END
  END b[86]
  PIN b[87]
    DIRECTION OUTPUT ;
    USE SIGNAL ;
    PORT
      LAYER M5 ;
        RECT  47.472 0 47.496 0.084 ;
    END
  END b[87]
  PIN b[88]
    DIRECTION OUTPUT ;
    USE SIGNAL ;
    PORT
      LAYER M5 ;
        RECT  47.568 0 47.592 0.084 ;
    END
  END b[88]
  PIN b[89]
    DIRECTION OUTPUT ;
    USE SIGNAL ;
    PORT
      LAYER M5 ;
        RECT  47.664 0 47.688 0.084 ;
    END
  END b[89]
  PIN b[8]
    DIRECTION OUTPUT ;
    USE SIGNAL ;
    PORT
      LAYER M5 ;
        RECT  29.904 0 29.928 0.084 ;
    END
  END b[8]
  PIN b[90]
    DIRECTION OUTPUT ;
    USE SIGNAL ;
    PORT
      LAYER M5 ;
        RECT  47.76 0 47.784 0.084 ;
    END
  END b[90]
  PIN b[91]
    DIRECTION OUTPUT ;
    USE SIGNAL ;
    PORT
      LAYER M5 ;
        RECT  47.856 0 47.88 0.084 ;
    END
  END b[91]
  PIN b[92]
    DIRECTION OUTPUT ;
    USE SIGNAL ;
    PORT
      LAYER M5 ;
        RECT  47.952 0 47.976 0.084 ;
    END
  END b[92]
  PIN b[93]
    DIRECTION OUTPUT ;
    USE SIGNAL ;
    PORT
      LAYER M5 ;
        RECT  48.048 0 48.072 0.084 ;
    END
  END b[93]
  PIN b[94]
    DIRECTION OUTPUT ;
    USE SIGNAL ;
    PORT
      LAYER M5 ;
        RECT  48.144 0 48.168 0.084 ;
    END
  END b[94]
  PIN b[95]
    DIRECTION OUTPUT ;
    USE SIGNAL ;
    PORT
      LAYER M5 ;
        RECT  48.24 0 48.264 0.084 ;
    END
  END b[95]
  PIN b[96]
    DIRECTION OUTPUT ;
    USE SIGNAL ;
    PORT
      LAYER M3 ;
        RECT  21.852 0 21.87 0.037 ;
    END
  END b[96]
  PIN b[97]
    DIRECTION OUTPUT ;
    USE SIGNAL ;
    PORT
      LAYER M3 ;
        RECT  21.924 0 21.942 0.037 ;
    END
  END b[97]
  PIN b[98]
    DIRECTION OUTPUT ;
    USE SIGNAL ;
    PORT
      LAYER M3 ;
        RECT  21.996 0 22.014 0.037 ;
    END
  END b[98]
  PIN b[99]
    DIRECTION OUTPUT ;
    USE SIGNAL ;
    PORT
      LAYER M3 ;
        RECT  22.068 0 22.086 0.037 ;
    END
  END b[99]
  PIN b[9]
    DIRECTION OUTPUT ;
    USE SIGNAL ;
    PORT
      LAYER M5 ;
        RECT  30 0 30.024 0.084 ;
    END
  END b[9]
  PIN ck
    DIRECTION INPUT ;
    USE SIGNAL ;
    PORT
      LAYER M4 ;
        RECT  64.692 13.2 64.776 13.224 ;
    END
  END ck
  PIN ck_s
    DIRECTION INPUT ;
    USE SIGNAL ;
    PORT
      LAYER M4 ;
        RECT  64.692 13.296 64.776 13.32 ;
    END
  END ck_s
  PIN en
    DIRECTION INPUT ;
    USE SIGNAL ;
    PORT
      LAYER M4 ;
        RECT  64.692 13.392 64.776 13.416 ;
    END
  END en
  PIN fault
    DIRECTION OUTPUT ;
    USE SIGNAL ;
    PORT
      LAYER M4 ;
        RECT  64.692 13.488 64.776 13.512 ;
    END
  END fault
  PIN k0
    DIRECTION INPUT ;
    USE SIGNAL ;
    PORT
      LAYER M4 ;
        RECT  64.692 13.584 64.776 13.608 ;
    END
  END k0
  PIN k1
    DIRECTION INPUT ;
    USE SIGNAL ;
    PORT
      LAYER M4 ;
        RECT  64.692 13.68 64.776 13.704 ;
    END
  END k1
  PIN k2
    DIRECTION INPUT ;
    USE SIGNAL ;
    PORT
      LAYER M4 ;
        RECT  64.692 13.776 64.776 13.8 ;
    END
  END k2
  PIN rs
    DIRECTION INPUT ;
    USE SIGNAL ;
    PORT
      LAYER M4 ;
        RECT  64.692 13.872 64.776 13.896 ;
    END
  END rs
  PIN tie_hi
    DIRECTION OUTPUT ;
    USE SIGNAL ;
    PORT
      LAYER M4 ;
        RECT  64.692 13.968 64.776 13.992 ;
    END
  END tie_hi
  PIN tie_lo
    DIRECTION OUTPUT ;
    USE SIGNAL ;
    PORT
      LAYER M4 ;
        RECT  64.692 14.064 64.776 14.088 ;
    END
  END tie_lo
  PIN VDD
    DIRECTION INOUT ;
    USE POWER ;
    PORT
      LAYER M5 ;
        RECT  61.992 2.151 62.112 27.833 ;
        RECT  59.292 2.151 59.412 27.833 ;
        RECT  56.592 2.151 56.712 27.833 ;
        RECT  53.892 2.151 54.012 27.833 ;
        RECT  51.192 2.151 51.312 27.833 ;
        RECT  48.492 2.151 48.612 27.833 ;
        RECT  45.792 2.151 45.912 27.833 ;
        RECT  43.092 2.151 43.212 27.833 ;
        RECT  40.392 2.151 40.512 27.833 ;
        RECT  37.692 2.151 37.812 27.833 ;
        RECT  34.992 2.151 35.112 27.833 ;
        RECT  32.292 2.151 32.412 27.833 ;
        RECT  29.592 2.151 29.712 27.833 ;
        RECT  26.892 2.151 27.012 27.833 ;
        RECT  24.192 2.151 24.312 27.833 ;
        RECT  21.492 2.151 21.612 27.833 ;
        RECT  18.792 2.151 18.912 27.833 ;
        RECT  16.092 2.151 16.212 27.833 ;
        RECT  13.392 2.151 13.512 27.833 ;
        RECT  10.692 2.151 10.812 27.833 ;
        RECT  7.992 2.151 8.112 27.833 ;
        RECT  5.292 2.151 5.412 27.833 ;
        RECT  2.592 2.151 2.712 27.833 ;
    END
  END VDD
  PIN VSS
    DIRECTION INOUT ;
    USE GROUND ;
    PORT
      LAYER M5 ;
        RECT  61.8 2.137 61.92 27.819 ;
        RECT  59.1 2.137 59.22 27.819 ;
        RECT  56.4 2.137 56.52 27.819 ;
        RECT  53.7 2.137 53.82 27.819 ;
        RECT  51 2.137 51.12 27.819 ;
        RECT  48.3 2.137 48.42 27.819 ;
        RECT  45.6 2.137 45.72 27.819 ;
        RECT  42.9 2.137 43.02 27.819 ;
        RECT  40.2 2.137 40.32 27.819 ;
        RECT  37.5 2.137 37.62 27.819 ;
        RECT  34.8 2.137 34.92 27.819 ;
        RECT  32.1 2.137 32.22 27.819 ;
        RECT  29.4 2.137 29.52 27.819 ;
        RECT  26.7 2.137 26.82 27.819 ;
        RECT  24 2.137 24.12 27.819 ;
        RECT  21.3 2.137 21.42 27.819 ;
        RECT  18.6 2.137 18.72 27.819 ;
        RECT  15.9 2.137 16.02 27.819 ;
        RECT  13.2 2.137 13.32 27.819 ;
        RECT  10.5 2.137 10.62 27.819 ;
        RECT  7.8 2.137 7.92 27.819 ;
        RECT  5.1 2.137 5.22 27.819 ;
        RECT  2.4 2.137 2.52 27.819 ;
    END
  END VSS
  OBS
    LAYER RVTN ;
     RECT  2.16 2.16 62.586 2.295 ;
     RECT  2.16 2.565 62.586 2.835 ;
     RECT  2.16 3.105 62.586 3.375 ;
     RECT  2.16 3.645 62.586 3.915 ;
     RECT  2.16 4.185 62.586 4.455 ;
     RECT  2.16 4.725 62.586 4.995 ;
     RECT  2.16 5.265 62.586 5.535 ;
     RECT  2.16 5.805 62.586 6.075 ;
     RECT  2.16 6.345 62.586 6.615 ;
     RECT  2.16 6.885 62.586 7.155 ;
     RECT  2.16 7.425 62.586 7.695 ;
     RECT  2.16 7.965 62.586 8.235 ;
     RECT  2.16 8.505 62.586 8.775 ;
     RECT  2.16 9.045 62.586 9.315 ;
     RECT  2.16 9.585 62.586 9.855 ;
     RECT  2.16 10.125 62.586 10.395 ;
     RECT  2.16 10.665 62.586 10.935 ;
     RECT  2.16 11.205 62.586 11.475 ;
     RECT  2.16 11.745 62.586 12.015 ;
     RECT  2.16 12.285 62.586 12.555 ;
     RECT  2.16 12.825 62.586 13.095 ;
     RECT  2.16 13.365 62.586 13.635 ;
     RECT  2.16 13.905 62.586 14.175 ;
     RECT  2.16 14.445 62.586 14.715 ;
     RECT  2.16 14.985 62.586 15.255 ;
     RECT  2.16 15.525 62.586 15.795 ;
     RECT  2.16 16.065 62.586 16.335 ;
     RECT  2.16 16.605 62.586 16.875 ;
     RECT  2.16 17.145 62.586 17.415 ;
     RECT  2.16 17.685 62.586 17.955 ;
     RECT  2.16 18.225 62.586 18.495 ;
     RECT  2.16 18.765 62.586 19.035 ;
     RECT  2.16 19.305 62.586 19.575 ;
     RECT  2.16 19.845 62.586 20.115 ;
     RECT  2.16 20.385 62.586 20.655 ;
     RECT  2.16 20.925 62.586 21.195 ;
     RECT  2.16 21.465 62.586 21.735 ;
     RECT  2.16 22.005 62.586 22.275 ;
     RECT  2.16 22.545 62.586 22.815 ;
     RECT  2.16 23.085 62.586 23.355 ;
     RECT  2.16 23.625 62.586 23.895 ;
     RECT  2.16 24.165 62.586 24.435 ;
     RECT  2.16 24.705 62.586 24.975 ;
     RECT  2.16 25.245 62.586 25.515 ;
     RECT  2.16 25.785 62.586 26.055 ;
     RECT  2.16 26.325 62.586 26.595 ;
     RECT  2.16 26.865 62.586 27.135 ;
     RECT  2.16 27.405 62.586 27.675 ;
    LAYER RVTP ;
     RECT  2.16 2.295 62.586 2.565 ;
     RECT  2.16 2.835 62.586 3.105 ;
     RECT  2.16 3.375 62.586 3.645 ;
     RECT  2.16 3.915 62.586 4.185 ;
     RECT  2.16 4.455 62.586 4.725 ;
     RECT  2.16 4.995 62.586 5.265 ;
     RECT  2.16 5.535 62.586 5.805 ;
     RECT  2.16 6.075 62.586 6.345 ;
     RECT  2.16 6.615 62.586 6.885 ;
     RECT  2.16 7.155 62.586 7.425 ;
     RECT  2.16 7.695 62.586 7.965 ;
     RECT  2.16 8.235 62.586 8.505 ;
     RECT  2.16 8.775 62.586 9.045 ;
     RECT  2.16 9.315 62.586 9.585 ;
     RECT  2.16 9.855 62.586 10.125 ;
     RECT  2.16 10.395 62.586 10.665 ;
     RECT  2.16 10.935 62.586 11.205 ;
     RECT  2.16 11.475 62.586 11.745 ;
     RECT  2.16 12.015 62.586 12.285 ;
     RECT  2.16 12.555 62.586 12.825 ;
     RECT  2.16 13.095 62.586 13.365 ;
     RECT  2.16 13.635 62.586 13.905 ;
     RECT  2.16 14.175 62.586 14.445 ;
     RECT  2.16 14.715 62.586 14.985 ;
     RECT  2.16 15.255 62.586 15.525 ;
     RECT  2.16 15.795 62.586 16.065 ;
     RECT  2.16 16.335 62.586 16.605 ;
     RECT  2.16 16.875 62.586 17.145 ;
     RECT  2.16 17.415 62.586 17.685 ;
     RECT  2.16 17.955 62.586 18.225 ;
     RECT  2.16 18.495 62.586 18.765 ;
     RECT  2.16 19.035 62.586 19.305 ;
     RECT  2.16 19.575 62.586 19.845 ;
     RECT  2.16 20.115 62.586 20.385 ;
     RECT  2.16 20.655 62.586 20.925 ;
     RECT  2.16 21.195 62.586 21.465 ;
     RECT  2.16 21.735 62.586 22.005 ;
     RECT  2.16 22.275 62.586 22.545 ;
     RECT  2.16 22.815 62.586 23.085 ;
     RECT  2.16 23.355 62.586 23.625 ;
     RECT  2.16 23.895 62.586 24.165 ;
     RECT  2.16 24.435 62.586 24.705 ;
     RECT  2.16 24.975 62.586 25.245 ;
     RECT  2.16 25.515 62.586 25.785 ;
     RECT  2.16 26.055 62.586 26.325 ;
     RECT  2.16 26.595 62.586 26.865 ;
     RECT  2.16 27.135 62.586 27.405 ;
     RECT  2.16 27.675 62.586 27.81 ;
    LAYER M1 ;
     RECT  2.16 2.151 62.586 27.819 ;
    LAYER M2 ;
     RECT  2.16 2.151 21.055 27.819 ;
     RECT  21.055 2.106 21.811 27.819 ;
     RECT  21.811 1.728 21.947 27.819 ;
     RECT  22.279 0.18 22.423 0.198 ;
     RECT  22.423 0.108 22.559 0.198 ;
     RECT  22.559 0.108 22.567 0.126 ;
     RECT  22.531 1.152 22.631 1.17 ;
     RECT  21.947 2.106 23.071 27.819 ;
     RECT  23.071 2.034 23.143 27.819 ;
     RECT  22.567 0.036 23.431 0.126 ;
     RECT  23.431 0.036 23.575 0.162 ;
     RECT  23.575 0.036 23.675 0.234 ;
     RECT  24.079 30.006 24.151 30.024 ;
     RECT  24.151 30.006 24.179 30.168 ;
     RECT  23.143 1.962 24.223 27.819 ;
     RECT  24.223 1.962 24.295 27.9 ;
     RECT  24.179 30.15 24.359 30.168 ;
     RECT  24.295 1.962 24.367 27.972 ;
     RECT  23.675 0.036 24.395 0.162 ;
     RECT  24.367 1.962 24.439 28.044 ;
     RECT  24.395 0.036 24.467 0.054 ;
     RECT  24.439 1.962 24.511 28.134 ;
     RECT  24.511 1.962 24.719 28.206 ;
     RECT  24.719 1.962 25.331 27.864 ;
     RECT  25.331 2.151 25.547 27.864 ;
     RECT  25.951 29.961 26.023 29.979 ;
     RECT  26.023 29.961 26.095 30.06 ;
     RECT  26.095 29.961 26.123 30.168 ;
     RECT  26.123 30.042 26.275 30.168 ;
     RECT  26.275 30.042 27.815 30.204 ;
     RECT  27.815 30.186 28.067 30.204 ;
     RECT  25.547 2.151 28.615 27.819 ;
     RECT  30.631 1.152 30.767 1.17 ;
     RECT  28.615 2.106 31.675 27.819 ;
     RECT  31.675 2.034 32.927 27.819 ;
     RECT  38.875 29.808 39.011 29.826 ;
     RECT  39.343 30.15 39.407 30.168 ;
     RECT  41.071 30.15 41.279 30.168 ;
     RECT  32.927 2.151 41.575 27.819 ;
     RECT  41.575 2.151 41.791 27.864 ;
     RECT  41.791 2.151 41.971 27.9 ;
     RECT  42.079 30.006 42.151 30.024 ;
     RECT  41.971 2.106 42.367 27.9 ;
     RECT  42.151 30.006 42.655 30.168 ;
     RECT  42.655 29.961 42.691 30.168 ;
     RECT  42.763 1.152 42.899 1.17 ;
     RECT  42.367 2.106 43.727 27.936 ;
     RECT  43.663 1.152 43.835 1.17 ;
     RECT  42.691 29.961 45.491 30.204 ;
     RECT  45.491 30.15 45.563 30.204 ;
     RECT  45.563 30.186 45.635 30.204 ;
     RECT  45.751 0.072 46.147 0.09 ;
     RECT  46.147 0.072 46.507 0.162 ;
     RECT  46.507 0.072 46.543 0.279 ;
     RECT  43.727 2.151 46.759 27.936 ;
     RECT  46.759 1.962 47.039 27.936 ;
     RECT  46.543 0.036 47.839 0.279 ;
     RECT  47.039 1.962 48.263 27.864 ;
     RECT  48.263 2.034 49.091 27.864 ;
     RECT  47.839 0.036 49.883 0.549 ;
     RECT  49.883 0.036 50.387 0.198 ;
     RECT  50.387 0.108 50.747 0.198 ;
     RECT  50.747 0.18 50.819 0.198 ;
     RECT  49.091 2.034 52.151 27.819 ;
     RECT  52.151 2.151 62.586 27.819 ;
     RECT  62.586 13.572 63.887 14.436 ;
     RECT  63.887 13.572 63.923 14.202 ;
     RECT  63.923 13.572 63.959 13.59 ;
    LAYER M3 ;
     RECT  21.852 0.012 24.102 0.031 ;
     RECT  21.852 0.031 24.462 0.091 ;
     RECT  45.756 0.067 45.774 0.091 ;
     RECT  46.548 0.031 46.566 0.091 ;
     RECT  49.5 0.067 49.518 0.091 ;
     RECT  50.364 0.031 50.382 0.091 ;
     RECT  45.756 0.091 46.566 0.103 ;
     RECT  49.5 0.091 50.382 0.103 ;
     RECT  49.5 0.103 50.742 0.139 ;
     RECT  49.32 0.139 50.742 0.175 ;
     RECT  49.32 0.175 50.814 0.187 ;
     RECT  45.756 0.103 47.034 0.269 ;
     RECT  45.756 0.269 46.89 0.317 ;
     RECT  47.772 0.175 47.79 0.461 ;
     RECT  48.708 0.187 50.814 0.472 ;
     RECT  47.844 0.472 50.814 0.509 ;
     RECT  42.876 0.091 44.946 0.523 ;
     RECT  47.844 0.509 47.862 0.557 ;
     RECT  42.876 0.523 45.162 0.571 ;
     RECT  21.852 0.091 24.822 1.723 ;
     RECT  29.016 0.091 31.266 1.723 ;
     RECT  42.192 0.571 45.162 1.723 ;
     RECT  45.972 0.317 46.89 1.723 ;
     RECT  29.016 1.723 32.49 1.915 ;
     RECT  33.624 1.771 33.642 1.915 ;
     RECT  21.816 1.723 24.822 1.957 ;
     RECT  48.708 0.509 50.814 1.957 ;
     RECT  48.24 1.957 50.814 2.029 ;
     RECT  29.016 1.915 33.642 2.101 ;
     RECT  42.192 1.723 46.89 2.101 ;
     RECT  21.06 2.101 21.078 2.143 ;
     RECT  21.816 1.957 25.326 2.143 ;
     RECT  47.988 2.029 50.814 2.143 ;
     RECT  13.215 2.143 13.305 2.191 ;
     RECT  41.976 2.101 46.962 2.191 ;
     RECT  47.988 2.143 51.105 2.191 ;
     RECT  41.976 2.191 51.105 2.263 ;
     RECT  21.06 2.143 25.326 2.299 ;
     RECT  28.62 2.101 33.642 2.299 ;
     RECT  15.915 2.143 16.005 2.335 ;
     RECT  13.215 2.191 13.842 2.371 ;
     RECT  15.228 2.335 16.005 2.371 ;
     RECT  18.615 2.143 18.705 2.371 ;
     RECT  21.06 2.299 25.722 2.371 ;
     RECT  26.715 2.143 26.805 2.371 ;
     RECT  2.415 2.143 2.505 2.413 ;
     RECT  5.115 2.143 5.205 2.413 ;
     RECT  7.815 2.143 7.905 2.413 ;
     RECT  10.515 2.143 10.605 2.413 ;
     RECT  21.06 2.371 26.805 2.413 ;
     RECT  34.815 2.143 34.905 2.413 ;
     RECT  37.515 2.143 37.605 2.413 ;
     RECT  40.215 2.143 40.305 2.413 ;
     RECT  41.76 2.263 51.105 2.413 ;
     RECT  53.715 2.143 53.805 2.413 ;
     RECT  56.415 2.143 56.505 2.413 ;
     RECT  59.115 2.143 59.205 2.413 ;
     RECT  61.815 2.143 61.905 2.413 ;
     RECT  17.532 2.371 17.838 2.461 ;
     RECT  18.615 2.371 19.242 2.461 ;
     RECT  13.104 2.371 14.274 2.497 ;
     RECT  15.192 2.371 16.362 2.497 ;
     RECT  13.104 2.497 16.362 2.569 ;
     RECT  17.532 2.461 19.242 2.569 ;
     RECT  28.62 2.299 33.93 2.605 ;
     RECT  34.815 2.413 35.097 2.605 ;
     RECT  11.952 2.605 11.97 2.641 ;
     RECT  13.104 2.569 19.242 2.641 ;
     RECT  20.124 2.605 20.142 2.641 ;
     RECT  28.62 2.605 35.097 2.641 ;
     RECT  11.844 2.641 11.97 2.731 ;
     RECT  41.76 2.413 51.297 2.731 ;
     RECT  10.515 2.413 10.797 2.767 ;
     RECT  11.844 2.731 12.258 2.767 ;
     RECT  13.104 2.641 20.142 2.839 ;
     RECT  21.06 2.413 26.997 2.839 ;
     RECT  11.844 2.767 12.366 2.869 ;
     RECT  13.104 2.839 26.997 2.869 ;
     RECT  10.515 2.767 11.034 2.911 ;
     RECT  11.844 2.869 26.997 2.911 ;
     RECT  41.652 2.731 51.297 2.911 ;
     RECT  40.215 2.413 40.497 3.073 ;
     RECT  39.78 3.073 40.662 3.109 ;
     RECT  41.508 2.911 51.297 3.109 ;
     RECT  54.72 2.803 54.738 3.109 ;
     RECT  28.404 2.641 35.097 3.181 ;
     RECT  37.515 2.413 37.797 3.181 ;
     RECT  10.515 2.911 26.997 3.299 ;
     RECT  28.008 3.181 35.097 3.379 ;
     RECT  38.772 3.271 39.006 3.451 ;
     RECT  39.78 3.109 51.297 3.451 ;
     RECT  27.972 3.379 35.097 3.541 ;
     RECT  38.772 3.451 51.297 3.577 ;
     RECT  27.972 3.541 35.154 3.721 ;
     RECT  27.972 3.721 35.298 3.811 ;
     RECT  27.972 3.811 35.874 3.847 ;
     RECT  36.828 3.181 37.797 3.847 ;
     RECT  53.715 2.413 53.997 3.919 ;
     RECT  27.972 3.847 37.797 3.991 ;
     RECT  38.592 3.577 51.297 3.991 ;
     RECT  10.515 3.299 12.33 4.081 ;
     RECT  13.068 3.299 26.997 4.081 ;
     RECT  53.064 3.919 53.997 4.153 ;
     RECT  27.972 3.991 51.297 4.189 ;
     RECT  10.515 4.081 26.997 4.261 ;
     RECT  27.936 4.189 51.297 4.261 ;
     RECT  10.515 4.261 51.297 4.495 ;
     RECT  52.128 2.029 52.146 4.495 ;
     RECT  10.515 4.495 52.146 4.793 ;
     RECT  58.284 3.721 58.302 4.927 ;
     RECT  15.768 4.793 52.146 4.955 ;
     RECT  54.72 3.109 55.386 5.269 ;
     RECT  10.515 4.793 14.67 5.539 ;
     RECT  15.768 4.955 21.798 5.773 ;
     RECT  10.515 5.539 14.778 5.809 ;
     RECT  15.588 5.773 21.798 5.809 ;
     RECT  10.515 5.809 21.798 5.845 ;
     RECT  22.536 4.955 52.146 5.845 ;
     RECT  10.515 5.845 52.146 5.971 ;
     RECT  53.028 4.153 53.997 5.971 ;
     RECT  10.515 5.971 53.997 6.269 ;
     RECT  11.628 6.269 53.997 6.511 ;
     RECT  54.72 5.269 55.602 6.511 ;
     RECT  11.628 6.511 55.602 6.691 ;
     RECT  56.415 2.413 56.697 6.691 ;
     RECT  11.628 6.691 56.697 6.817 ;
     RECT  57.564 4.927 58.302 6.817 ;
     RECT  11.628 6.817 58.302 6.889 ;
     RECT  59.115 2.413 59.397 6.889 ;
     RECT  11.628 6.889 59.397 6.917 ;
     RECT  11.808 6.917 59.397 8.069 ;
     RECT  12.276 8.069 59.397 8.477 ;
     RECT  61.815 2.413 62.097 10.633 ;
     RECT  12.564 8.477 59.397 11.399 ;
     RECT  12.924 11.399 59.397 11.947 ;
     RECT  12.924 11.947 59.454 11.975 ;
     RECT  36.684 11.975 59.454 12.181 ;
     RECT  12.924 11.975 35.91 12.209 ;
     RECT  15.192 12.209 35.91 12.659 ;
     RECT  36.684 12.181 59.562 12.865 ;
     RECT  61.524 10.633 62.097 13.027 ;
     RECT  61.524 13.027 62.262 13.099 ;
     RECT  36.684 12.865 60.354 13.441 ;
     RECT  12.924 12.209 14.382 13.469 ;
     RECT  15.192 12.659 35.838 13.483 ;
     RECT  36.684 13.441 60.642 13.483 ;
     RECT  61.524 13.099 62.73 13.483 ;
     RECT  61.524 13.483 63.306 13.567 ;
     RECT  15.192 13.483 60.642 13.595 ;
     RECT  36.684 13.595 60.642 13.675 ;
     RECT  61.524 13.567 63.954 13.675 ;
     RECT  36.684 13.675 63.954 13.901 ;
     RECT  63.288 13.901 63.954 13.997 ;
     RECT  63.288 13.997 63.918 14.099 ;
     RECT  63.864 14.099 63.918 14.207 ;
     RECT  15.192 13.595 35.838 14.395 ;
     RECT  36.684 13.901 62.37 14.395 ;
     RECT  63.864 14.207 63.882 14.441 ;
     RECT  15.192 14.395 62.37 15.061 ;
     RECT  15.192 15.061 62.406 15.719 ;
     RECT  15.192 15.719 18.954 15.989 ;
     RECT  19.728 15.719 62.097 16.259 ;
     RECT  13.215 13.469 14.382 16.267 ;
     RECT  15.192 15.989 18.897 16.267 ;
     RECT  61.056 16.259 62.097 16.403 ;
     RECT  13.215 16.267 18.897 16.439 ;
     RECT  19.728 16.259 60.282 16.601 ;
     RECT  19.728 16.601 48.834 16.799 ;
     RECT  49.68 16.601 60.282 16.799 ;
     RECT  19.764 16.799 48.834 17.105 ;
     RECT  19.764 17.105 36.018 17.339 ;
     RECT  36.756 17.105 48.834 17.347 ;
     RECT  49.68 16.799 59.814 17.347 ;
     RECT  19.764 17.339 22.086 17.375 ;
     RECT  36.756 17.347 59.814 17.375 ;
     RECT  22.932 17.339 36.018 17.519 ;
     RECT  14.94 16.439 18.897 17.653 ;
     RECT  19.764 17.375 21.69 17.653 ;
     RECT  36.756 17.375 59.742 17.879 ;
     RECT  23.004 17.519 36.018 18.031 ;
     RECT  36.756 17.879 54.09 18.031 ;
     RECT  14.94 17.653 21.69 18.229 ;
     RECT  54.828 17.879 59.742 18.257 ;
     RECT  14.94 18.229 22.194 18.535 ;
     RECT  23.004 18.031 54.09 18.535 ;
     RECT  54.828 18.257 59.397 18.563 ;
     RECT  14.94 18.535 54.09 18.769 ;
     RECT  54.828 18.563 58.374 18.769 ;
     RECT  61.056 16.403 61.074 18.869 ;
     RECT  14.94 18.769 58.374 19.111 ;
     RECT  13.215 16.439 13.986 19.139 ;
     RECT  14.832 19.111 58.374 19.181 ;
     RECT  14.832 19.181 21.942 19.345 ;
     RECT  22.716 19.181 58.374 19.499 ;
     RECT  22.716 19.499 58.158 19.607 ;
     RECT  34.344 19.607 58.158 19.769 ;
     RECT  34.344 19.769 58.122 19.913 ;
     RECT  34.344 19.913 57.762 19.949 ;
     RECT  34.344 19.949 57.222 20.039 ;
     RECT  14.724 19.345 21.942 20.155 ;
     RECT  22.716 19.607 33.57 20.155 ;
     RECT  34.344 20.039 57.078 20.309 ;
     RECT  34.344 20.309 56.697 20.695 ;
     RECT  14.724 20.155 33.57 20.731 ;
     RECT  34.308 20.695 56.697 20.731 ;
     RECT  14.724 20.731 56.697 21.119 ;
     RECT  14.724 21.119 54.522 21.299 ;
     RECT  15.696 21.299 54.522 21.425 ;
     RECT  34.704 21.425 54.522 21.461 ;
     RECT  34.704 21.461 36.054 21.569 ;
     RECT  36.9 21.461 54.522 21.569 ;
     RECT  34.704 21.569 35.982 21.929 ;
     RECT  34.704 21.929 35.838 21.965 ;
     RECT  15.696 21.425 33.714 22.013 ;
     RECT  34.704 21.965 35.73 22.109 ;
     RECT  23.148 22.013 33.714 22.315 ;
     RECT  34.704 22.109 35.406 22.315 ;
     RECT  23.148 22.315 35.406 22.343 ;
     RECT  23.148 22.343 35.19 22.469 ;
     RECT  23.148 22.469 35.097 22.505 ;
     RECT  23.796 22.505 35.097 22.649 ;
     RECT  23.796 22.649 32.397 22.739 ;
     RECT  37.404 21.569 54.522 22.739 ;
     RECT  33.12 22.649 35.097 22.775 ;
     RECT  33.336 22.775 35.097 23.009 ;
     RECT  53.244 22.739 54.522 23.009 ;
     RECT  33.336 23.009 33.354 23.045 ;
     RECT  23.94 22.739 32.397 23.189 ;
     RECT  15.696 22.013 21.942 23.279 ;
     RECT  37.404 22.739 52.47 23.279 ;
     RECT  31.14 23.189 32.397 23.315 ;
     RECT  23.94 23.189 30.366 23.549 ;
     RECT  23.94 23.549 30.294 23.585 ;
     RECT  20.772 23.279 21.942 23.819 ;
     RECT  34.164 23.009 35.097 23.819 ;
     RECT  23.94 23.585 30.186 23.899 ;
     RECT  37.515 23.279 52.362 24.359 ;
     RECT  14.724 21.299 14.886 24.629 ;
     RECT  21.276 23.819 21.942 24.899 ;
     RECT  31.14 23.315 31.158 24.899 ;
     RECT  21.276 24.899 21.597 25.015 ;
     RECT  15.696 23.279 19.962 25.169 ;
     RECT  52.2 24.359 52.362 25.169 ;
     RECT  23.832 23.899 30.186 25.241 ;
     RECT  23.832 25.241 28.314 25.439 ;
     RECT  33.3 23.827 33.318 25.709 ;
     RECT  14.868 24.629 14.886 25.817 ;
     RECT  15.696 25.169 19.854 26.051 ;
     RECT  15.915 26.051 19.854 26.095 ;
     RECT  15.915 26.095 20.07 26.141 ;
     RECT  30.996 25.015 31.014 26.249 ;
     RECT  37.515 24.359 51.462 26.563 ;
     RECT  52.236 25.169 52.362 26.563 ;
     RECT  23.976 25.439 28.314 26.635 ;
     RECT  55.656 21.119 56.697 26.789 ;
     RECT  37.515 26.563 52.362 26.905 ;
     RECT  29.088 25.241 30.186 27.059 ;
     RECT  55.656 26.789 55.674 27.059 ;
     RECT  15.915 26.141 19.854 27.175 ;
     RECT  29.088 27.059 29.697 27.175 ;
     RECT  37.515 26.905 52.578 27.329 ;
     RECT  53.715 23.009 54.522 27.329 ;
     RECT  37.515 27.329 52.362 27.365 ;
     RECT  23.94 26.635 28.314 27.401 ;
     RECT  50.292 27.365 52.362 27.509 ;
     RECT  2.415 2.413 2.697 27.557 ;
     RECT  5.115 2.413 5.397 27.557 ;
     RECT  7.815 2.413 8.097 27.557 ;
     RECT  10.515 6.269 10.797 27.557 ;
     RECT  13.215 19.139 13.497 27.557 ;
     RECT  15.915 27.175 19.962 27.557 ;
     RECT  32.115 23.315 32.397 27.557 ;
     RECT  34.815 23.819 35.097 27.557 ;
     RECT  37.515 27.365 49.518 27.557 ;
     RECT  50.292 27.509 52.218 27.557 ;
     RECT  53.715 27.329 54.27 27.557 ;
     RECT  56.415 26.789 56.697 27.557 ;
     RECT  59.115 18.563 59.397 27.557 ;
     RECT  61.815 16.403 62.097 27.557 ;
     RECT  16.107 27.557 19.962 27.599 ;
     RECT  23.112 27.481 23.13 27.599 ;
     RECT  29.052 27.175 29.697 27.599 ;
     RECT  50.292 27.557 50.31 27.599 ;
     RECT  51.207 27.557 52.218 27.599 ;
     RECT  55.26 27.175 55.278 27.599 ;
     RECT  52.2 27.599 52.218 27.635 ;
     RECT  37.707 27.557 49.518 27.707 ;
     RECT  53.907 27.557 54.27 27.707 ;
     RECT  37.707 27.707 47.034 27.773 ;
     RECT  23.94 27.401 28.062 27.779 ;
     RECT  47.844 27.707 49.518 27.779 ;
     RECT  2.607 27.557 2.697 27.827 ;
     RECT  5.307 27.557 5.397 27.827 ;
     RECT  8.007 27.557 8.097 27.827 ;
     RECT  10.707 27.557 10.797 27.827 ;
     RECT  13.407 27.557 13.497 27.827 ;
     RECT  16.107 27.599 19.746 27.827 ;
     RECT  21.024 25.015 21.597 27.827 ;
     RECT  23.94 27.779 26.997 27.827 ;
     RECT  29.607 27.599 29.697 27.827 ;
     RECT  32.307 27.557 32.397 27.827 ;
     RECT  35.007 27.557 35.097 27.827 ;
     RECT  37.707 27.773 37.797 27.827 ;
     RECT  48.507 27.779 49.086 27.827 ;
     RECT  51.207 27.599 51.297 27.827 ;
     RECT  53.907 27.707 53.997 27.827 ;
     RECT  56.607 27.557 56.697 27.827 ;
     RECT  59.307 27.557 59.397 27.827 ;
     RECT  62.007 27.557 62.097 27.827 ;
     RECT  16.236 27.827 19.746 27.869 ;
     RECT  38.556 27.773 47.034 27.869 ;
     RECT  49.068 27.827 49.086 27.869 ;
     RECT  43.992 27.869 47.034 27.905 ;
     RECT  16.236 27.869 19.494 27.917 ;
     RECT  38.556 27.869 43.254 27.917 ;
     RECT  44.316 27.905 45.63 27.941 ;
     RECT  47.016 27.905 47.034 27.941 ;
     RECT  17.82 27.917 19.35 28.445 ;
     RECT  17.82 28.445 19.17 28.493 ;
     RECT  17.82 28.493 17.838 28.541 ;
     RECT  38.556 27.917 42.822 29.659 ;
     RECT  16.236 27.917 17.01 29.741 ;
     RECT  16.236 29.741 16.254 29.789 ;
     RECT  38.34 29.659 42.822 29.956 ;
     RECT  45.468 27.941 45.63 29.984 ;
     RECT  27.792 27.779 28.062 30.065 ;
     RECT  44.496 27.941 44.586 30.065 ;
     RECT  23.94 27.827 26.226 30.073 ;
     RECT  44.568 30.065 44.586 30.101 ;
     RECT  16.992 29.741 17.01 30.125 ;
     RECT  21.024 27.827 21.042 30.125 ;
     RECT  45.54 29.984 45.63 30.173 ;
     RECT  23.94 30.073 26.298 30.204 ;
     RECT  38.34 29.956 42.894 30.204 ;
     RECT  26.28 30.204 26.298 30.209 ;
     RECT  28.044 30.065 28.062 30.209 ;
     RECT  42.696 30.204 42.714 30.209 ;
     RECT  45.612 30.173 45.63 30.209 ;
    LAYER M4 ;
     RECT  2.408 2.148 2.512 27.552 ;
     RECT  2.512 2.418 2.6 27.552 ;
     RECT  2.6 2.418 2.704 27.822 ;
     RECT  5.108 2.148 5.212 27.552 ;
     RECT  5.212 2.418 5.3 27.552 ;
     RECT  5.3 2.418 5.404 27.822 ;
     RECT  7.808 2.148 7.912 27.552 ;
     RECT  7.912 2.418 8 27.552 ;
     RECT  8 2.418 8.104 27.822 ;
     RECT  10.508 2.148 10.612 27.552 ;
     RECT  10.612 2.418 10.7 27.552 ;
     RECT  10.7 2.418 10.804 27.822 ;
     RECT  10.804 3.984 11.905 4.536 ;
     RECT  11.797 6.864 12.121 6.888 ;
     RECT  11.905 3.984 12.125 4.68 ;
     RECT  12.121 6.864 12.265 7.704 ;
     RECT  11.905 2.88 12.301 2.904 ;
     RECT  12.265 5.856 12.877 5.88 ;
     RECT  12.265 6.864 12.877 8.472 ;
     RECT  12.125 4.464 13.201 4.68 ;
     RECT  12.301 2.88 13.208 3.096 ;
     RECT  13.201 4.128 13.208 4.68 ;
     RECT  12.877 5.856 13.208 8.472 ;
     RECT  13.208 2.148 13.312 27.552 ;
     RECT  13.312 2.418 13.4 27.552 ;
     RECT  13.4 2.418 13.504 27.822 ;
     RECT  13.504 2.88 13.565 4.68 ;
     RECT  13.565 2.88 13.889 4.152 ;
     RECT  13.504 5.712 13.889 8.472 ;
     RECT  13.504 9.552 14.285 9.576 ;
     RECT  13.889 5.712 14.501 7.8 ;
     RECT  14.501 5.712 14.645 7.128 ;
     RECT  13.889 2.88 14.861 3.336 ;
     RECT  14.861 3.024 14.929 3.336 ;
     RECT  14.929 3.024 15.361 3.864 ;
     RECT  15.361 3.024 15.469 4.152 ;
     RECT  15.469 3.024 15.908 4.392 ;
     RECT  14.645 5.856 15.908 7.128 ;
     RECT  13.504 11.424 15.908 11.448 ;
     RECT  15.781 26.016 15.908 26.04 ;
     RECT  15.781 27.408 15.908 27.432 ;
     RECT  15.908 2.148 16.012 27.552 ;
     RECT  16.012 2.418 16.1 27.552 ;
     RECT  16.1 2.418 16.204 27.822 ;
     RECT  16.225 29.76 16.261 29.784 ;
     RECT  16.204 2.592 16.409 7.944 ;
     RECT  16.204 10.176 16.589 11.448 ;
     RECT  16.204 25.872 16.741 27.822 ;
     RECT  16.261 29.664 16.883 29.784 ;
     RECT  16.204 12.528 17.02 14.088 ;
     RECT  16.409 2.592 17.068 7.128 ;
     RECT  16.204 24.768 17.075 24.792 ;
     RECT  16.589 10.176 17.137 10.872 ;
     RECT  16.741 25.872 17.197 27.912 ;
     RECT  17.068 2.736 17.453 7.128 ;
     RECT  17.137 10.176 17.485 10.632 ;
     RECT  17.413 24.48 17.497 24.504 ;
     RECT  17.453 2.736 17.561 4.008 ;
     RECT  17.453 5.136 17.593 7.128 ;
     RECT  17.197 25.632 17.605 27.912 ;
     RECT  16.981 30.096 17.651 30.12 ;
     RECT  17.605 26.4 17.765 27.912 ;
     RECT  17.02 12.528 17.845 13.32 ;
     RECT  17.765 26.4 17.874 28.536 ;
     RECT  17.593 5.136 17.953 7.224 ;
     RECT  17.561 2.736 18.529 2.856 ;
     RECT  17.561 3.84 18.529 4.008 ;
     RECT  18.529 2.736 18.608 4.008 ;
     RECT  17.953 5.136 18.608 7.656 ;
     RECT  17.485 9.36 18.608 10.632 ;
     RECT  17.845 11.952 18.608 13.32 ;
     RECT  17.485 14.304 18.608 15.048 ;
     RECT  17.874 26.4 18.608 28.488 ;
     RECT  18.608 2.148 18.712 28.488 ;
     RECT  18.712 2.418 18.904 28.488 ;
     RECT  18.904 13.872 18.965 13.896 ;
     RECT  18.904 5.76 19.043 10.632 ;
     RECT  18.949 29.904 19.045 29.928 ;
     RECT  19.045 29.904 19.091 30.024 ;
     RECT  19.091 30 19.141 30.024 ;
     RECT  19.043 9.6 19.145 10.632 ;
     RECT  18.904 3.12 19.181 3.96 ;
     RECT  18.904 26.64 19.181 28.488 ;
     RECT  19.141 30 19.187 30.12 ;
     RECT  19.181 3.312 19.253 3.96 ;
     RECT  18.904 11.952 19.289 12.792 ;
     RECT  19.253 3.312 19.325 3.336 ;
     RECT  19.181 26.64 19.361 28.44 ;
     RECT  18.904 15.024 19.397 15.432 ;
     RECT  19.361 26.64 19.397 27.912 ;
     RECT  19.397 27.36 19.505 27.912 ;
     RECT  19.505 27.36 19.757 27.864 ;
     RECT  19.757 27.36 19.955 27.816 ;
     RECT  19.043 5.76 20.081 8.472 ;
     RECT  19.909 26.112 20.081 26.136 ;
     RECT  19.145 9.696 20.149 10.632 ;
     RECT  20.149 9.696 20.257 11.352 ;
     RECT  19.289 12.528 20.293 12.792 ;
     RECT  20.257 9.696 20.389 11.544 ;
     RECT  20.293 12.528 20.389 13.704 ;
     RECT  20.081 5.808 20.473 8.472 ;
     RECT  20.389 9.696 20.473 13.704 ;
     RECT  19.187 30.096 21.053 30.12 ;
     RECT  20.977 3.84 21.085 3.864 ;
     RECT  19.397 15.408 21.109 15.432 ;
     RECT  21.085 3.84 21.157 4.68 ;
     RECT  20.473 5.808 21.157 13.704 ;
     RECT  21.157 3.84 21.308 13.704 ;
     RECT  21.109 15.408 21.308 15.48 ;
     RECT  21.085 17.088 21.308 17.64 ;
     RECT  19.955 27.792 21.308 27.816 ;
     RECT  21.308 2.148 21.412 27.816 ;
     RECT  21.412 2.256 21.5 27.816 ;
     RECT  21.5 2.256 21.604 27.822 ;
     RECT  21.604 12.528 21.665 13.56 ;
     RECT  21.665 12.768 21.779 13.56 ;
     RECT  21.604 3.408 21.809 5.688 ;
     RECT  21.604 7.296 21.845 11.544 ;
     RECT  21.845 7.296 22.097 9.096 ;
     RECT  21.604 17.088 22.211 20.328 ;
     RECT  22.211 17.088 22.457 17.112 ;
     RECT  22.211 18.528 22.597 20.328 ;
     RECT  21.604 2.256 22.669 2.28 ;
     RECT  21.809 3.408 22.669 4.68 ;
     RECT  21.604 15.888 22.669 15.912 ;
     RECT  21.845 10.224 22.741 11.544 ;
     RECT  21.779 12.912 22.741 13.56 ;
     RECT  22.741 10.224 22.781 13.56 ;
     RECT  22.597 18.528 22.787 20.568 ;
     RECT  22.097 7.296 22.853 7.896 ;
     RECT  22.781 10.224 22.853 10.344 ;
     RECT  21.809 5.664 22.957 5.688 ;
     RECT  22.781 11.52 22.997 13.56 ;
     RECT  22.787 18.528 22.997 20.424 ;
     RECT  22.597 21.984 23.132 22.008 ;
     RECT  23.132 21.984 23.173 22.488 ;
     RECT  22.853 7.296 23.281 7.32 ;
     RECT  22.997 18.528 23.317 19.368 ;
     RECT  22.669 2.256 23.461 4.68 ;
     RECT  22.957 5.664 23.461 6.12 ;
     RECT  22.669 15.888 23.461 16.008 ;
     RECT  23.317 18.24 23.461 19.368 ;
     RECT  23.713 0.096 23.785 0.12 ;
     RECT  23.461 2.256 23.857 6.12 ;
     RECT  23.281 7.152 23.857 7.32 ;
     RECT  23.785 0.048 23.893 0.12 ;
     RECT  23.461 15.312 23.893 16.008 ;
     RECT  23.461 17.472 23.893 19.368 ;
     RECT  23.893 0.048 23.933 0.168 ;
     RECT  23.857 2.256 24.008 7.32 ;
     RECT  22.097 8.976 24.008 9.096 ;
     RECT  22.853 10.32 24.008 10.344 ;
     RECT  22.997 11.52 24.008 12.552 ;
     RECT  23.353 13.584 24.008 13.608 ;
     RECT  23.893 15.312 24.008 19.368 ;
     RECT  22.997 20.4 24.008 20.424 ;
     RECT  23.173 21.792 24.008 22.488 ;
     RECT  24.008 2.148 24.112 27.552 ;
     RECT  24.112 2.418 24.2 27.552 ;
     RECT  24.2 2.418 24.304 27.822 ;
     RECT  24.304 2.592 24.419 6.6 ;
     RECT  24.304 21.792 24.419 22.824 ;
     RECT  24.304 10.32 24.545 12.552 ;
     RECT  24.304 13.584 24.545 14.232 ;
     RECT  24.545 10.896 24.617 12.552 ;
     RECT  24.419 22.176 24.617 22.824 ;
     RECT  24.545 14.208 24.625 14.232 ;
     RECT  23.933 0.096 24.689 0.168 ;
     RECT  24.419 2.592 24.748 4.872 ;
     RECT  24.689 0.096 24.833 0.12 ;
     RECT  24.793 29.664 24.865 29.688 ;
     RECT  24.617 22.176 24.941 22.2 ;
     RECT  24.304 25.872 25.036 26.136 ;
     RECT  24.304 17.472 25.049 18.552 ;
     RECT  25.036 26.112 25.091 26.136 ;
     RECT  24.419 6.096 25.229 6.6 ;
     RECT  24.617 10.896 25.265 11.64 ;
     RECT  24.304 15.312 25.445 15.336 ;
     RECT  24.865 29.664 25.475 30.168 ;
     RECT  25.429 26.4 25.477 26.664 ;
     RECT  24.304 27.744 25.477 27.768 ;
     RECT  24.748 2.88 25.513 4.872 ;
     RECT  25.513 2.88 25.525 5.112 ;
     RECT  25.475 29.664 25.571 30.12 ;
     RECT  25.265 11.376 25.621 11.64 ;
     RECT  24.304 16.416 25.621 16.44 ;
     RECT  25.477 20.352 25.657 20.376 ;
     RECT  25.477 9.12 25.667 9.144 ;
     RECT  25.621 16.368 25.693 16.44 ;
     RECT  25.657 13.104 25.729 13.128 ;
     RECT  25.657 20.304 25.801 20.376 ;
     RECT  25.729 13.104 25.837 13.224 ;
     RECT  25.571 29.664 25.859 29.784 ;
     RECT  25.837 13.056 25.861 13.224 ;
     RECT  25.859 29.712 25.955 29.784 ;
     RECT  25.861 13.056 26.005 13.512 ;
     RECT  25.955 29.76 26.195 29.784 ;
     RECT  26.005 12.912 26.197 13.512 ;
     RECT  25.049 18.192 26.197 18.552 ;
     RECT  25.801 20.304 26.197 20.568 ;
     RECT  26.197 12.816 26.233 13.512 ;
     RECT  25.525 2.88 26.269 5.976 ;
     RECT  25.621 7.392 26.269 7.8 ;
     RECT  25.693 15.456 26.413 16.44 ;
     RECT  26.269 2.88 26.708 7.8 ;
     RECT  26.101 9.36 26.708 9.384 ;
     RECT  25.621 11.376 26.708 11.688 ;
     RECT  26.233 12.816 26.708 13.704 ;
     RECT  26.413 15.456 26.708 17.16 ;
     RECT  26.197 18.192 26.708 20.568 ;
     RECT  25.873 23.04 26.708 23.064 ;
     RECT  25.477 26.4 26.708 27.768 ;
     RECT  26.708 2.148 26.812 27.768 ;
     RECT  26.812 2.418 26.9 27.768 ;
     RECT  26.9 2.418 27.004 27.822 ;
     RECT  27.004 9.36 27.217 16.536 ;
     RECT  27.217 11.136 27.244 16.536 ;
     RECT  27.004 6.576 27.389 7.992 ;
     RECT  27.244 11.952 27.389 16.536 ;
     RECT  27.004 23.04 27.389 23.064 ;
     RECT  27.389 14.4 27.425 16.536 ;
     RECT  27.425 14.4 27.713 15.48 ;
     RECT  27.004 18.192 27.965 19.08 ;
     RECT  27.965 18.336 28.145 19.08 ;
     RECT  27.217 9.36 28.249 9.384 ;
     RECT  28.145 18.432 28.316 19.08 ;
     RECT  27.713 14.4 28.325 15.288 ;
     RECT  27.389 6.624 28.361 6.84 ;
     RECT  28.249 9.072 28.537 9.384 ;
     RECT  28.537 9.072 28.609 9.576 ;
     RECT  28.393 2.688 28.645 2.712 ;
     RECT  27.004 3.84 28.645 5.064 ;
     RECT  28.105 22.752 28.681 22.776 ;
     RECT  28.609 9.072 28.741 10.248 ;
     RECT  28.645 2.688 28.789 5.064 ;
     RECT  27.004 21.072 28.988 21.096 ;
     RECT  28.316 18.432 28.997 19.224 ;
     RECT  29.005 0.096 29.077 0.12 ;
     RECT  28.789 2.688 29.077 5.16 ;
     RECT  28.325 14.736 29.132 15.288 ;
     RECT  29.132 14.736 29.185 15.432 ;
     RECT  27.425 16.512 29.185 16.536 ;
     RECT  29.077 2.688 29.257 5.736 ;
     RECT  28.997 18.432 29.257 19.944 ;
     RECT  28.988 20.976 29.257 21.096 ;
     RECT  29.077 0.096 29.267 0.6 ;
     RECT  29.185 14.736 29.269 16.536 ;
     RECT  27.389 11.952 29.293 13.128 ;
     RECT  29.257 1.776 29.317 5.736 ;
     RECT  27.389 7.872 29.401 7.992 ;
     RECT  28.741 8.976 29.401 10.248 ;
     RECT  29.317 1.728 29.408 5.736 ;
     RECT  29.401 7.872 29.408 10.248 ;
     RECT  29.293 11.952 29.408 13.656 ;
     RECT  29.269 14.736 29.408 17.064 ;
     RECT  29.257 18.432 29.408 21.096 ;
     RECT  28.681 22.752 29.408 22.824 ;
     RECT  29.408 1.728 29.6 27.552 ;
     RECT  29.6 1.728 29.704 27.822 ;
     RECT  29.704 1.728 29.729 4.68 ;
     RECT  29.704 19.344 29.909 19.368 ;
     RECT  29.729 2.88 30.017 4.68 ;
     RECT  29.704 14.736 30.017 15.288 ;
     RECT  29.704 22.8 30.017 22.824 ;
     RECT  30.017 2.88 30.233 4.392 ;
     RECT  29.704 8.496 30.305 9.576 ;
     RECT  29.267 0.096 30.545 0.12 ;
     RECT  29.704 16.368 30.593 16.392 ;
     RECT  30.545 0.096 30.661 0.168 ;
     RECT  30.661 0.096 30.773 0.6 ;
     RECT  29.704 11.952 30.809 13.656 ;
     RECT  30.305 9.36 30.845 9.576 ;
     RECT  30.809 12.816 31.061 13.656 ;
     RECT  30.017 15.024 31.061 15.288 ;
     RECT  29.729 1.728 31.141 1.848 ;
     RECT  29.704 20.88 31.165 21.72 ;
     RECT  30.773 0.096 31.187 0.312 ;
     RECT  31.129 18.672 31.201 18.696 ;
     RECT  31.141 1.728 31.237 1.896 ;
     RECT  31.187 0.096 31.283 0.216 ;
     RECT  31.283 0.096 31.321 0.12 ;
     RECT  31.201 16.896 31.333 16.92 ;
     RECT  31.201 18 31.333 18.696 ;
     RECT  31.237 1.728 31.561 1.944 ;
     RECT  30.233 3.168 31.561 4.392 ;
     RECT  31.561 1.728 31.849 4.392 ;
     RECT  31.561 6.24 31.849 6.264 ;
     RECT  31.165 20.4 31.885 21.72 ;
     RECT  31.333 16.896 31.909 18.696 ;
     RECT  31.909 16.896 31.921 18.744 ;
     RECT  31.849 1.728 31.993 6.264 ;
     RECT  31.813 7.968 31.993 7.992 ;
     RECT  31.993 1.728 32.108 7.992 ;
     RECT  30.845 9.552 32.108 9.576 ;
     RECT  31.093 10.56 32.108 10.584 ;
     RECT  31.061 12.816 32.108 13.464 ;
     RECT  31.061 15.216 32.108 15.288 ;
     RECT  31.921 16.656 32.108 18.744 ;
     RECT  31.885 20.4 32.108 21.816 ;
     RECT  32.108 1.728 32.3 27.552 ;
     RECT  32.3 1.728 32.404 27.822 ;
     RECT  32.404 1.728 32.429 2.568 ;
     RECT  32.429 1.728 32.501 2.52 ;
     RECT  32.404 16.416 32.609 22.248 ;
     RECT  32.404 3.552 32.723 5.592 ;
     RECT  32.404 15.264 32.897 15.384 ;
     RECT  32.723 4.656 33.005 5.592 ;
     RECT  32.897 15.264 33.005 15.336 ;
     RECT  32.609 16.416 33.059 21.144 ;
     RECT  33.059 16.992 33.077 21.144 ;
     RECT  32.609 22.224 33.149 22.248 ;
     RECT  33.005 4.752 33.221 5.592 ;
     RECT  32.501 1.776 33.251 2.52 ;
     RECT  32.723 3.552 33.329 3.576 ;
     RECT  32.404 9.12 33.401 9.672 ;
     RECT  32.404 7.2 33.505 7.416 ;
     RECT  33.251 1.776 33.653 2.328 ;
     RECT  33.401 9.408 33.653 9.672 ;
     RECT  32.404 12.816 33.685 12.84 ;
     RECT  33.653 9.408 33.797 9.576 ;
     RECT  33.005 15.264 34.045 15.288 ;
     RECT  33.685 12.816 34.069 13.272 ;
     RECT  32.404 11.136 34.081 11.16 ;
     RECT  34.081 11.136 34.165 11.256 ;
     RECT  33.077 16.992 34.165 19.416 ;
     RECT  33.221 5.088 34.189 5.592 ;
     RECT  34.189 5.088 34.225 6.024 ;
     RECT  33.505 7.2 34.225 8.232 ;
     RECT  34.069 12.528 34.585 13.272 ;
     RECT  34.225 5.088 34.801 8.232 ;
     RECT  33.797 9.408 34.801 9.48 ;
     RECT  33.653 2.304 34.808 2.328 ;
     RECT  34.261 3.84 34.808 3.864 ;
     RECT  34.801 5.088 34.808 9.48 ;
     RECT  34.165 11.136 34.808 11.448 ;
     RECT  34.585 12.528 34.808 13.704 ;
     RECT  34.045 15.264 34.808 15.384 ;
     RECT  34.165 16.56 34.808 19.416 ;
     RECT  33.077 20.496 34.808 21.144 ;
     RECT  34.808 2.148 34.912 27.552 ;
     RECT  34.912 2.418 35 27.552 ;
     RECT  35 2.418 35.104 27.822 ;
     RECT  35.104 14.784 35.345 15.288 ;
     RECT  35.104 18.432 35.381 21.288 ;
     RECT  35.104 16.56 35.489 16.584 ;
     RECT  35.104 3.84 35.705 6.888 ;
     RECT  35.381 19.2 35.795 21.288 ;
     RECT  35.795 21.12 35.813 21.288 ;
     RECT  35.705 3.84 35.891 5.256 ;
     RECT  35.705 6.864 35.921 6.888 ;
     RECT  35.795 19.2 35.921 19.992 ;
     RECT  35.104 12.816 35.987 13.608 ;
     RECT  35.891 4.464 35.993 5.256 ;
     RECT  35.987 13.488 36.083 13.608 ;
     RECT  35.104 10.992 36.097 11.256 ;
     RECT  36.097 10.992 36.101 11.688 ;
     RECT  36.101 11.136 36.245 11.688 ;
     RECT  36.169 9.696 36.421 9.72 ;
     RECT  36.083 13.584 36.421 13.608 ;
     RECT  35.345 14.976 36.421 15.288 ;
     RECT  36.421 9.072 36.467 9.72 ;
     RECT  36.467 9.072 36.565 9.336 ;
     RECT  36.245 11.424 36.889 11.688 ;
     RECT  35.813 21.12 37.141 21.192 ;
     RECT  35.993 5.232 37.393 5.256 ;
     RECT  36.421 13.584 37.465 15.288 ;
     RECT  37.393 4.512 37.508 5.256 ;
     RECT  36.565 8.16 37.508 9.336 ;
     RECT  36.889 11.424 37.508 12.216 ;
     RECT  37.465 13.584 37.508 15.576 ;
     RECT  36.745 17.472 37.508 17.496 ;
     RECT  35.921 19.2 37.508 19.32 ;
     RECT  37.141 20.4 37.508 21.192 ;
     RECT  37.508 2.148 37.612 27.552 ;
     RECT  37.612 2.418 37.7 27.552 ;
     RECT  37.7 2.418 37.804 27.822 ;
     RECT  37.804 8.16 38.225 13.608 ;
     RECT  38.225 8.208 38.243 13.608 ;
     RECT  38.101 29.664 38.245 29.688 ;
     RECT  38.245 29.664 38.437 29.832 ;
     RECT  37.804 18.672 38.513 20.424 ;
     RECT  37.804 17.088 38.627 17.592 ;
     RECT  38.513 18.672 38.627 19.608 ;
     RECT  38.627 17.472 38.649 17.592 ;
     RECT  37.804 24.96 38.729 25.128 ;
     RECT  37.804 3.312 38.819 5.256 ;
     RECT  38.819 3.312 38.845 3.72 ;
     RECT  38.819 5.088 38.881 5.256 ;
     RECT  38.243 8.208 38.909 9.672 ;
     RECT  38.909 8.208 38.981 8.616 ;
     RECT  37.804 26.112 39.049 27.768 ;
     RECT  39.049 26.112 39.133 27.912 ;
     RECT  38.729 25.056 39.161 25.128 ;
     RECT  39.133 26.112 39.205 27.768 ;
     RECT  37.804 14.736 39.229 15.576 ;
     RECT  38.909 9.648 39.349 9.672 ;
     RECT  38.243 10.752 39.349 13.608 ;
     RECT  38.649 17.568 39.481 17.592 ;
     RECT  38.881 5.232 39.685 5.256 ;
     RECT  37.804 6.24 39.685 6.264 ;
     RECT  39.481 17.568 39.805 18.12 ;
     RECT  38.627 19.296 39.805 19.608 ;
     RECT  39.229 14.736 39.884 16.296 ;
     RECT  39.884 14.736 39.97 16.584 ;
     RECT  39.805 17.568 39.97 19.608 ;
     RECT  39.97 14.736 39.973 19.608 ;
     RECT  39.877 20.592 39.973 20.616 ;
     RECT  39.205 25.296 40.117 27.768 ;
     RECT  38.845 3.648 40.208 3.72 ;
     RECT  39.685 5.232 40.208 6.264 ;
     RECT  38.981 8.448 40.208 8.616 ;
     RECT  39.349 9.648 40.208 13.608 ;
     RECT  39.973 14.736 40.208 20.616 ;
     RECT  40.117 25.296 40.208 27.912 ;
     RECT  40.208 2.148 40.312 27.912 ;
     RECT  40.312 2.418 40.385 27.912 ;
     RECT  40.385 2.418 40.504 27.822 ;
     RECT  40.504 16.608 40.565 21.528 ;
     RECT  40.504 25.44 40.601 27.768 ;
     RECT  40.504 14.736 40.673 15.576 ;
     RECT  40.504 3.312 40.853 7.416 ;
     RECT  40.853 6 40.889 7.416 ;
     RECT  40.504 8.448 40.889 10.344 ;
     RECT  40.889 9.456 41.027 10.344 ;
     RECT  40.565 16.656 41.033 21.528 ;
     RECT  41.027 9.552 41.069 10.344 ;
     RECT  40.504 11.424 41.069 11.544 ;
     RECT  41.033 16.656 41.097 19.944 ;
     RECT  41.097 16.656 41.105 19.416 ;
     RECT  40.601 25.584 41.105 27.768 ;
     RECT  40.853 3.312 41.497 4.68 ;
     RECT  40.504 12.864 41.497 13.608 ;
     RECT  41.105 25.872 41.509 27.768 ;
     RECT  41.497 12.624 41.557 13.608 ;
     RECT  38.437 29.664 41.603 30.168 ;
     RECT  41.497 3.072 41.645 4.68 ;
     RECT  40.889 6.192 41.749 7.416 ;
     RECT  40.889 8.448 41.749 8.472 ;
     RECT  41.645 3.072 41.789 3.96 ;
     RECT  41.105 17.04 41.897 17.064 ;
     RECT  41.509 25.872 41.941 27.864 ;
     RECT  41.603 30.144 41.987 30.168 ;
     RECT  41.749 6.192 42.037 8.472 ;
     RECT  42.037 5.088 42.073 8.472 ;
     RECT  41.069 9.648 42.073 10.344 ;
     RECT  42.181 0.576 42.217 0.6 ;
     RECT  42.217 0.576 42.323 0.696 ;
     RECT  42.073 5.088 42.433 10.344 ;
     RECT  41.557 11.904 42.433 13.608 ;
     RECT  42.505 1.728 42.649 1.752 ;
     RECT  41.789 3.072 42.649 3.624 ;
     RECT  41.941 25.872 42.661 27.912 ;
     RECT  42.433 5.088 42.685 13.608 ;
     RECT  42.649 1.728 42.793 3.624 ;
     RECT  42.323 0.576 42.821 0.6 ;
     RECT  42.793 1.68 42.908 3.624 ;
     RECT  42.685 5.088 42.908 13.704 ;
     RECT  40.673 14.976 42.908 15.576 ;
     RECT  41.105 18.576 42.908 19.416 ;
     RECT  41.033 21.504 42.908 21.528 ;
     RECT  42.661 25.728 42.908 27.912 ;
     RECT  42.821 0.096 42.995 0.6 ;
     RECT  42.908 1.68 43.187 27.912 ;
     RECT  43.187 1.728 43.204 27.912 ;
     RECT  43.204 1.728 43.265 6.84 ;
     RECT  43.204 27.888 43.265 27.912 ;
     RECT  43.265 1.728 43.337 2.904 ;
     RECT  43.204 8.448 43.445 15.288 ;
     RECT  43.445 8.448 43.517 8.52 ;
     RECT  43.265 3.936 43.571 6.84 ;
     RECT  43.204 17.04 43.619 19.416 ;
     RECT  43.204 25.968 43.667 26.904 ;
     RECT  43.571 5.856 43.805 6.84 ;
     RECT  43.571 3.936 43.985 4.536 ;
     RECT  43.517 8.496 44.129 8.52 ;
     RECT  43.445 9.552 44.147 15.288 ;
     RECT  43.667 26.64 44.197 26.904 ;
     RECT  44.197 26.64 44.201 27.672 ;
     RECT  43.337 2.304 44.243 2.904 ;
     RECT  43.619 17.04 44.345 17.064 ;
     RECT  44.147 13.104 44.413 15.288 ;
     RECT  42.995 0.096 44.485 0.552 ;
     RECT  44.201 26.736 44.525 27.672 ;
     RECT  43.619 18.048 44.557 19.416 ;
     RECT  43.204 20.448 44.557 20.76 ;
     RECT  44.413 13.104 44.561 15.864 ;
     RECT  44.485 0.096 44.569 0.6 ;
     RECT  44.557 18.048 44.593 20.76 ;
     RECT  44.525 26.784 44.669 27.672 ;
     RECT  43.204 23.904 44.773 23.928 ;
     RECT  44.243 2.304 44.92 2.856 ;
     RECT  44.92 2.256 44.945 2.856 ;
     RECT  44.593 18.048 44.981 21 ;
     RECT  44.593 25.104 44.989 25.128 ;
     RECT  44.773 23.184 45.013 23.928 ;
     RECT  44.989 24.96 45.013 25.128 ;
     RECT  45.025 8.448 45.061 8.472 ;
     RECT  44.569 0.096 45.203 0.552 ;
     RECT  44.981 18.048 45.205 21.144 ;
     RECT  44.147 9.552 45.397 12.024 ;
     RECT  44.561 13.104 45.397 13.608 ;
     RECT  45.013 23.184 45.493 25.128 ;
     RECT  43.985 4.512 45.529 4.536 ;
     RECT  44.561 14.688 45.565 15.864 ;
     RECT  45.529 3.84 45.601 4.536 ;
     RECT  43.805 6.048 45.601 6.84 ;
     RECT  44.945 1.728 45.608 2.856 ;
     RECT  45.601 3.84 45.608 6.84 ;
     RECT  45.061 7.872 45.608 8.472 ;
     RECT  45.397 9.552 45.608 13.608 ;
     RECT  45.565 14.688 45.608 16.584 ;
     RECT  45.205 18.048 45.608 22.056 ;
     RECT  45.493 23.184 45.608 25.752 ;
     RECT  44.669 26.784 45.608 27.624 ;
     RECT  45.608 1.728 45.8 27.624 ;
     RECT  45.8 1.728 45.904 27.822 ;
     RECT  45.904 1.728 45.965 7.176 ;
     RECT  45.904 25.632 46.001 25.752 ;
     RECT  45.904 18.192 46.019 20.088 ;
     RECT  45.965 1.728 46.109 6.936 ;
     RECT  46.019 18.192 46.109 19.992 ;
     RECT  45.904 8.448 46.145 8.472 ;
     RECT  45.904 15.264 46.253 16.584 ;
     RECT  46.109 18.192 46.289 19.896 ;
     RECT  45.904 26.784 46.289 27.624 ;
     RECT  46.253 16.56 46.325 16.584 ;
     RECT  46.289 18.192 46.325 19.56 ;
     RECT  46.289 26.784 46.397 27.384 ;
     RECT  46.325 18.384 46.649 19.56 ;
     RECT  45.904 12.864 46.721 13.608 ;
     RECT  45.203 0.096 46.729 0.456 ;
     RECT  45.904 9.552 46.793 11.448 ;
     RECT  45.904 22.032 46.865 22.056 ;
     RECT  46.109 2.208 46.933 6.936 ;
     RECT  46.001 25.632 46.973 25.656 ;
     RECT  46.793 9.6 47.045 11.208 ;
     RECT  46.933 2.208 47.089 7.224 ;
     RECT  47.089 2.256 47.18 7.224 ;
     RECT  46.397 26.832 47.189 27.384 ;
     RECT  47.18 2.256 47.267 7.32 ;
     RECT  46.253 15.264 47.329 15.576 ;
     RECT  46.729 0.096 47.717 0.408 ;
     RECT  47.717 0.096 47.833 0.456 ;
     RECT  47.437 17.136 47.869 17.16 ;
     RECT  47.113 22.464 47.869 22.776 ;
     RECT  47.437 20.688 47.9 20.712 ;
     RECT  47.869 22.464 47.9 22.824 ;
     RECT  47.833 0.096 47.917 0.552 ;
     RECT  47.267 2.256 48.133 7.224 ;
     RECT  46.649 18.384 48.149 19.32 ;
     RECT  47.9 20.688 48.149 22.824 ;
     RECT  47.329 15.024 48.157 15.576 ;
     RECT  48.157 15.024 48.265 15.864 ;
     RECT  47.869 17.136 48.265 17.4 ;
     RECT  47.917 0.096 48.305 0.504 ;
     RECT  48.133 2.064 48.308 7.224 ;
     RECT  47.413 8.208 48.308 8.232 ;
     RECT  47.045 9.792 48.308 11.208 ;
     RECT  46.721 13.104 48.308 13.608 ;
     RECT  48.265 15.024 48.308 17.4 ;
     RECT  48.149 18.384 48.308 22.824 ;
     RECT  47.113 25.056 48.308 25.08 ;
     RECT  47.189 26.832 48.308 26.856 ;
     RECT  48.308 2.064 48.5 27.552 ;
     RECT  48.5 2.064 48.604 27.822 ;
     RECT  48.604 2.064 48.845 7.128 ;
     RECT  48.604 14.736 48.845 16.392 ;
     RECT  48.604 8.208 48.989 11.16 ;
     RECT  48.989 8.208 49.025 9.096 ;
     RECT  48.845 15.264 49.061 16.392 ;
     RECT  48.604 20.544 49.061 21.432 ;
     RECT  48.845 2.304 49.091 7.128 ;
     RECT  49.091 2.304 49.132 5.208 ;
     RECT  48.989 10.32 49.169 11.16 ;
     RECT  49.025 8.208 49.277 8.472 ;
     RECT  49.061 15.264 49.457 15.288 ;
     RECT  49.091 6.192 49.523 7.128 ;
     RECT  48.604 17.376 49.633 17.4 ;
     RECT  49.132 2.304 49.673 3.624 ;
     RECT  49.061 16.368 49.813 16.392 ;
     RECT  49.633 17.376 49.813 17.688 ;
     RECT  48.305 0.096 49.853 0.456 ;
     RECT  49.169 10.32 49.853 10.872 ;
     RECT  48.604 19.296 49.921 19.56 ;
     RECT  49.061 20.544 49.921 20.568 ;
     RECT  49.673 3.6 49.955 3.624 ;
     RECT  49.132 4.656 49.961 5.208 ;
     RECT  49.961 4.656 49.996 5.064 ;
     RECT  48.604 22.8 50.021 22.824 ;
     RECT  50.021 22.224 50.06 22.824 ;
     RECT  49.523 6.288 50.101 7.128 ;
     RECT  49.277 8.208 50.101 8.376 ;
     RECT  49.813 16.368 50.101 17.688 ;
     RECT  49.853 10.656 50.149 10.872 ;
     RECT  50.101 16.368 50.149 17.88 ;
     RECT  49.921 19.296 50.149 20.568 ;
     RECT  50.06 22.128 50.149 22.824 ;
     RECT  49.853 0.144 50.177 0.456 ;
     RECT  50.177 0.288 50.357 0.456 ;
     RECT  48.604 12.192 50.533 13.608 ;
     RECT  50.357 0.288 50.609 0.408 ;
     RECT  50.609 0.288 50.717 0.312 ;
     RECT  50.149 10.656 50.785 11.112 ;
     RECT  50.533 12.192 50.785 14.232 ;
     RECT  49.673 2.304 51.008 2.376 ;
     RECT  49.996 5.04 51.008 5.064 ;
     RECT  50.101 6.288 51.008 8.376 ;
     RECT  50.785 10.656 51.008 14.232 ;
     RECT  50.749 15.36 51.008 15.384 ;
     RECT  50.149 16.368 51.008 20.568 ;
     RECT  50.149 21.936 51.008 22.824 ;
     RECT  50.821 23.856 51.008 23.88 ;
     RECT  51.008 2.148 51.112 27.552 ;
     RECT  51.112 2.418 51.2 27.552 ;
     RECT  51.2 2.418 51.304 27.822 ;
     RECT  51.304 16.272 51.401 17.16 ;
     RECT  51.304 13.104 51.653 14.856 ;
     RECT  51.304 18.144 51.797 18.168 ;
     RECT  51.304 19.296 51.869 21.144 ;
     RECT  51.304 9.6 51.905 9.624 ;
     RECT  51.304 22.176 52.307 23.976 ;
     RECT  52.307 22.176 52.348 23.16 ;
     RECT  52.348 22.176 52.355 22.824 ;
     RECT  51.653 14.832 52.373 14.856 ;
     RECT  52.355 22.8 52.381 22.824 ;
     RECT  51.869 19.296 52.397 19.512 ;
     RECT  52.397 18.768 52.451 19.512 ;
     RECT  51.869 20.544 52.451 21.144 ;
     RECT  51.304 6.384 52.499 8.424 ;
     RECT  52.499 7.296 52.54 8.424 ;
     RECT  52.54 7.44 52.553 8.424 ;
     RECT  51.304 12 52.553 12.024 ;
     RECT  52.553 7.44 52.589 8.232 ;
     RECT  51.304 10.656 52.621 10.68 ;
     RECT  51.653 13.104 52.729 13.608 ;
     RECT  51.401 16.272 52.789 16.632 ;
     RECT  52.789 16.272 53.017 17.064 ;
     RECT  52.621 10.176 53.161 11.016 ;
     RECT  52.589 7.632 53.557 8.232 ;
     RECT  53.017 16.272 53.557 17.64 ;
     RECT  52.451 18.768 53.557 19.32 ;
     RECT  53.557 7.632 53.708 8.52 ;
     RECT  53.161 9.504 53.708 11.016 ;
     RECT  52.729 12.096 53.708 13.608 ;
     RECT  53.557 16.272 53.708 19.32 ;
     RECT  52.451 21.12 53.708 21.144 ;
     RECT  53.708 2.148 53.812 27.552 ;
     RECT  53.812 2.418 53.9 27.552 ;
     RECT  53.9 2.418 54.004 27.822 ;
     RECT  54.004 10.176 54.173 20.04 ;
     RECT  54.004 21.12 54.179 21.144 ;
     RECT  54.173 10.224 54.209 20.04 ;
     RECT  54.209 17.088 54.707 20.04 ;
     RECT  54.209 10.224 54.713 15.816 ;
     RECT  54.713 12.864 55.145 15.816 ;
     RECT  54.004 7.632 55.283 9.096 ;
     RECT  54.713 10.224 55.283 11.448 ;
     RECT  55.145 12.864 55.361 13.848 ;
     RECT  55.145 15.456 55.397 15.816 ;
     RECT  55.397 15.456 55.433 15.48 ;
     RECT  55.283 7.632 56.408 8.328 ;
     RECT  55.283 10.224 56.408 11.16 ;
     RECT  55.361 12.864 56.408 13.608 ;
     RECT  56.221 14.976 56.408 15 ;
     RECT  54.707 17.136 56.408 20.04 ;
     RECT  56.408 2.148 56.512 27.552 ;
     RECT  56.512 2.418 56.6 27.552 ;
     RECT  56.6 2.418 56.704 27.822 ;
     RECT  56.704 10.704 57.161 11.4 ;
     RECT  56.704 17.088 57.233 18.216 ;
     RECT  57.233 17.136 57.269 18.216 ;
     RECT  57.269 17.136 57.665 17.208 ;
     RECT  56.704 14.928 57.697 15.48 ;
     RECT  56.704 19.92 57.773 19.944 ;
     RECT  57.697 14.928 57.841 15.96 ;
     RECT  56.704 7.2 57.845 8.568 ;
     RECT  57.161 11.376 57.913 11.4 ;
     RECT  56.704 12.528 57.913 13.608 ;
     RECT  57.841 14.88 57.913 15.96 ;
     RECT  57.665 17.184 58.561 17.208 ;
     RECT  57.269 18.192 58.561 18.216 ;
     RECT  57.913 14.88 58.645 16.008 ;
     RECT  58.561 17.184 58.645 18.216 ;
     RECT  57.913 11.376 59.065 13.608 ;
     RECT  57.845 7.632 59.108 8.568 ;
     RECT  57.949 9.936 59.108 9.96 ;
     RECT  59.065 11.376 59.108 13.704 ;
     RECT  58.645 14.88 59.108 18.216 ;
     RECT  59.108 2.148 59.212 27.552 ;
     RECT  59.212 2.418 59.3 27.552 ;
     RECT  59.3 2.418 59.404 27.822 ;
     RECT  59.404 14.928 59.465 14.952 ;
     RECT  59.404 13.104 61.808 13.704 ;
     RECT  61.037 14.832 61.808 14.856 ;
     RECT  61.808 2.148 61.912 27.552 ;
     RECT  61.912 2.418 62 27.552 ;
     RECT  62 2.418 62.104 27.822 ;
     RECT  62.104 13.104 62.741 13.896 ;
     RECT  62.741 13.2 63.277 13.896 ;
     RECT  63.277 13.2 64.716 14.088 ;
    LAYER M5 ;
     RECT  29.136 0.016 32.136 0.131 ;
     RECT  42.192 0.016 48.264 0.515 ;
     RECT  29.232 0.131 32.136 0.611 ;
     RECT  42.192 0.515 48.072 0.611 ;
     RECT  42.288 0.611 48.072 0.707 ;
     RECT  29.328 0.611 32.136 1.763 ;
     RECT  29.4 1.763 32.136 1.765 ;
     RECT  29.4 1.765 32.232 1.859 ;
     RECT  31.152 1.859 32.232 1.907 ;
     RECT  31.248 1.907 32.232 1.955 ;
     RECT  42.384 0.707 48.072 2.053 ;
     RECT  42.384 2.053 48.168 2.137 ;
     RECT  2.4 2.137 2.52 2.151 ;
     RECT  5.1 2.137 5.22 2.151 ;
     RECT  7.8 2.137 7.92 2.151 ;
     RECT  10.5 2.137 10.62 2.151 ;
     RECT  13.2 2.137 13.32 2.151 ;
     RECT  15.9 2.137 16.02 2.151 ;
     RECT  18.6 2.137 18.72 2.151 ;
     RECT  21.3 2.137 21.42 2.151 ;
     RECT  24 2.137 24.12 2.151 ;
     RECT  26.7 2.137 26.82 2.151 ;
     RECT  31.632 1.955 32.232 2.151 ;
     RECT  34.8 2.137 34.92 2.151 ;
     RECT  37.5 2.137 37.62 2.151 ;
     RECT  40.2 2.137 40.32 2.151 ;
     RECT  42.384 2.137 48.42 2.151 ;
     RECT  51 2.137 51.12 2.151 ;
     RECT  53.7 2.137 53.82 2.151 ;
     RECT  56.4 2.137 56.52 2.151 ;
     RECT  59.1 2.137 59.22 2.151 ;
     RECT  61.8 2.137 61.92 2.151 ;
     RECT  31.632 2.151 32.412 2.197 ;
     RECT  31.632 2.197 33.24 2.339 ;
     RECT  42.384 2.151 48.612 2.387 ;
     RECT  15.9 2.151 16.212 2.581 ;
     RECT  24 2.151 24.312 2.581 ;
     RECT  29.4 1.859 29.832 2.725 ;
     RECT  44.208 2.387 48.612 2.867 ;
     RECT  26.7 2.151 27.012 2.869 ;
     RECT  44.208 2.867 44.232 2.915 ;
     RECT  29.088 2.725 29.832 3.157 ;
     RECT  29.088 3.157 30.792 3.443 ;
     RECT  42.384 2.387 43.212 3.443 ;
     RECT  42.48 3.443 43.212 3.491 ;
     RECT  32.1 2.339 33.24 3.587 ;
     RECT  24 2.581 24.696 3.685 ;
     RECT  34.8 2.151 35.112 3.829 ;
     RECT  15.9 2.581 17.016 3.875 ;
     RECT  30.768 3.443 30.792 4.019 ;
     RECT  24 3.685 24.984 4.165 ;
     RECT  26.16 2.869 27.012 4.165 ;
     RECT  42.768 3.491 43.212 4.261 ;
     RECT  45.6 2.867 48.612 4.261 ;
     RECT  49.92 3.589 49.944 4.261 ;
     RECT  21.3 2.151 21.612 4.501 ;
     RECT  24 4.165 27.012 4.501 ;
     RECT  23.904 4.501 27.012 4.547 ;
     RECT  38.784 3.301 38.808 4.547 ;
     RECT  13.2 2.151 13.512 4.645 ;
     RECT  45.6 4.261 49.944 4.691 ;
     RECT  32.1 3.587 32.712 5.077 ;
     RECT  23.904 4.547 24.408 5.171 ;
     RECT  34.8 3.829 35.88 5.171 ;
     RECT  21.168 4.501 21.612 5.219 ;
     RECT  32.1 5.077 33.672 5.267 ;
     RECT  24 5.171 24.408 5.315 ;
     RECT  42.768 4.261 43.56 5.507 ;
     RECT  38.832 5.077 38.856 5.605 ;
     RECT  40.2 2.151 40.512 5.605 ;
     RECT  15.9 3.875 16.212 5.701 ;
     RECT  17.424 5.125 17.448 5.701 ;
     RECT  25.536 4.547 27.012 5.747 ;
     RECT  29.088 3.443 29.712 5.747 ;
     RECT  15.9 5.701 17.448 5.749 ;
     RECT  45.6 4.691 49.512 5.795 ;
     RECT  15.9 5.749 17.592 5.891 ;
     RECT  45.6 5.795 46.056 6.085 ;
     RECT  32.1 5.267 32.412 6.229 ;
     RECT  38.832 5.605 40.512 6.275 ;
     RECT  21.3 5.219 21.612 6.277 ;
     RECT  42.768 5.507 43.212 6.277 ;
     RECT  51 2.151 51.312 6.277 ;
     RECT  47.088 5.795 49.512 6.323 ;
     RECT  47.232 6.323 49.512 6.373 ;
     RECT  50.88 6.277 51.312 6.373 ;
     RECT  18.6 2.151 18.912 6.805 ;
     RECT  20.544 6.277 21.612 6.805 ;
     RECT  15.9 5.891 17.016 6.851 ;
     RECT  47.232 6.373 51.312 7.139 ;
     RECT  47.232 7.139 48.936 7.331 ;
     RECT  50.112 7.139 51.312 7.379 ;
     RECT  33.648 5.267 33.672 7.381 ;
     RECT  34.8 5.171 35.112 7.381 ;
     RECT  33.648 7.381 35.112 7.427 ;
     RECT  59.1 2.151 59.412 7.621 ;
     RECT  25.824 5.747 27.012 7.765 ;
     RECT  29.4 5.747 29.712 7.861 ;
     RECT  42.096 6.277 43.212 7.957 ;
     RECT  37.5 2.151 37.812 8.197 ;
     RECT  38.832 6.275 38.856 8.197 ;
     RECT  47.424 7.331 48.936 8.243 ;
     RECT  37.5 8.197 38.856 8.339 ;
     RECT  50.736 7.379 51.312 8.341 ;
     RECT  50.688 8.341 51.312 8.389 ;
     RECT  52.464 6.373 52.488 8.389 ;
     RECT  50.688 8.389 52.488 8.435 ;
     RECT  13.104 4.645 13.512 8.483 ;
     RECT  53.7 2.151 54.012 8.485 ;
     RECT  38.832 8.339 38.856 8.579 ;
     RECT  25.632 7.765 27.012 9.155 ;
     RECT  41.76 7.957 43.212 9.155 ;
     RECT  37.5 8.339 37.812 9.349 ;
     RECT  33.888 7.427 35.112 9.443 ;
     RECT  39.936 6.275 40.512 9.445 ;
     RECT  41.76 9.155 41.784 9.445 ;
     RECT  50.688 8.435 51.864 9.635 ;
     RECT  36.432 9.061 36.456 9.731 ;
     RECT  15.9 6.851 16.212 10.165 ;
     RECT  25.824 9.155 27.012 10.213 ;
     RECT  53.568 8.485 54.012 10.355 ;
     RECT  39.936 9.445 41.784 10.453 ;
     RECT  18.6 6.805 21.612 10.595 ;
     RECT  45.312 6.085 46.056 10.645 ;
     RECT  42.9 9.155 43.212 10.693 ;
     RECT  45.12 10.645 46.056 10.789 ;
     RECT  15.9 10.165 17.112 10.883 ;
     RECT  34.176 9.443 35.112 10.981 ;
     RECT  53.7 10.355 54.012 10.981 ;
     RECT  50.688 9.635 51.312 11.077 ;
     RECT  42.9 10.693 43.32 11.365 ;
     RECT  44.64 10.789 46.056 11.365 ;
     RECT  37.5 9.349 38.232 11.413 ;
     RECT  34.176 10.981 35.208 11.459 ;
     RECT  37.056 11.413 38.232 11.459 ;
     RECT  55.248 9.061 55.272 11.459 ;
     RECT  24 5.315 24.312 11.461 ;
     RECT  25.824 10.213 27.192 11.461 ;
     RECT  24 11.461 27.192 11.651 ;
     RECT  20.544 10.595 21.612 11.845 ;
     RECT  18.6 10.595 18.912 11.941 ;
     RECT  28.752 7.861 29.712 11.987 ;
     RECT  39.36 10.453 41.784 12.035 ;
     RECT  53.7 10.981 54.12 12.035 ;
     RECT  25.824 11.651 27.192 12.083 ;
     RECT  37.056 11.459 37.812 12.227 ;
     RECT  29.04 11.987 29.712 12.373 ;
     RECT  18.192 11.941 18.912 12.517 ;
     RECT  34.8 11.459 35.208 12.517 ;
     RECT  58.992 7.621 59.412 12.517 ;
     RECT  20.4 11.845 21.612 12.563 ;
     RECT  39.36 12.035 41.592 12.659 ;
     RECT  21.12 12.563 21.612 12.757 ;
     RECT  34.08 12.517 35.208 12.805 ;
     RECT  48.3 8.243 48.936 12.997 ;
     RECT  29.04 12.373 30.408 13.139 ;
     RECT  39.36 12.659 41.016 13.139 ;
     RECT  48.3 12.997 49.032 13.235 ;
     RECT  50.16 11.077 51.312 13.235 ;
     RECT  34.08 12.805 35.976 13.283 ;
     RECT  58.032 12.517 59.412 13.283 ;
     RECT  15.9 10.883 16.212 13.285 ;
     RECT  17.664 12.517 18.912 13.285 ;
     RECT  34.608 13.283 35.976 13.477 ;
     RECT  21.12 12.757 21.768 13.523 ;
     RECT  58.032 13.283 58.056 13.523 ;
     RECT  29.4 13.139 30.408 13.667 ;
     RECT  61.8 2.151 62.112 13.669 ;
     RECT  34.608 13.477 36.072 13.715 ;
     RECT  42.9 11.365 46.056 13.811 ;
     RECT  15.9 13.285 18.912 14.099 ;
     RECT  24 11.651 24.312 14.197 ;
     RECT  17.664 14.099 18.912 14.339 ;
     RECT  29.4 13.667 29.712 14.725 ;
     RECT  61.056 13.669 62.112 14.867 ;
     RECT  34.8 13.715 36.072 15.011 ;
     RECT  44.496 13.811 46.056 15.203 ;
     RECT  24 14.197 24.6 15.301 ;
     RECT  23.904 15.301 24.6 15.347 ;
     RECT  34.8 15.011 35.112 15.349 ;
     RECT  29.184 14.725 29.712 15.443 ;
     RECT  21.12 13.523 21.612 15.491 ;
     RECT  53.7 12.035 54.012 16.261 ;
     RECT  50.736 13.235 51.312 16.357 ;
     RECT  31.92 6.229 32.412 16.405 ;
     RECT  39.936 13.139 40.512 16.595 ;
     RECT  31.92 16.405 33.048 16.885 ;
     RECT  59.1 13.283 59.412 16.933 ;
     RECT  28.368 16.501 28.392 17.029 ;
     RECT  29.4 15.443 29.712 17.029 ;
     RECT  52.8 16.261 54.012 17.075 ;
     RECT  21.3 15.491 21.612 17.077 ;
     RECT  37.5 12.227 37.812 17.077 ;
     RECT  53.7 17.075 54.012 17.077 ;
     RECT  31.344 16.885 33.048 17.125 ;
     RECT  34.176 15.349 35.112 17.125 ;
     RECT  31.344 17.125 35.112 17.219 ;
     RECT  48.3 13.235 48.936 17.365 ;
     RECT  23.904 15.347 24.312 17.507 ;
     RECT  42.9 13.811 43.212 17.605 ;
     RECT  56.4 2.151 56.712 17.605 ;
     RECT  33.6 17.219 35.112 17.651 ;
     RECT  58.656 16.933 59.412 17.699 ;
     RECT  39.984 16.595 40.512 18.037 ;
     RECT  56.4 17.605 57 18.227 ;
     RECT  42.9 17.605 43.608 18.229 ;
     RECT  44.592 15.203 46.056 18.229 ;
     RECT  28.368 17.029 29.712 18.467 ;
     RECT  31.344 17.219 32.412 18.565 ;
     RECT  33.6 17.651 33.624 18.565 ;
     RECT  31.344 18.565 33.624 18.707 ;
     RECT  37.5 17.077 38.616 18.707 ;
     RECT  31.92 18.707 33.624 18.755 ;
     RECT  21.3 17.077 22.2 19.141 ;
     RECT  53.7 17.077 54.696 19.141 ;
     RECT  42.9 18.229 46.056 19.331 ;
     RECT  39.888 18.037 40.512 19.381 ;
     RECT  42.9 19.331 43.944 19.427 ;
     RECT  48.192 17.365 48.936 19.427 ;
     RECT  21.3 19.141 22.584 19.909 ;
     RECT  28.368 18.467 28.392 19.909 ;
     RECT  29.4 18.467 29.712 19.909 ;
     RECT  37.5 18.707 37.812 19.909 ;
     RECT  39.888 19.381 41.064 19.955 ;
     RECT  34.8 17.651 35.112 19.957 ;
     RECT  21.3 19.909 22.776 20.003 ;
     RECT  45.024 19.331 46.056 20.003 ;
     RECT  53.7 19.141 55.272 20.003 ;
     RECT  53.7 20.003 54.696 20.051 ;
     RECT  45.024 20.003 46.008 20.099 ;
     RECT  42.9 19.427 43.212 20.437 ;
     RECT  45.024 20.099 45.912 20.437 ;
     RECT  22.752 20.003 22.776 20.579 ;
     RECT  25.824 12.083 27.012 20.579 ;
     RECT  52.416 18.757 52.44 20.579 ;
     RECT  39.888 19.955 40.512 20.627 ;
     RECT  48.192 19.427 48.888 20.677 ;
     RECT  42.9 20.437 45.912 20.771 ;
     RECT  34.8 19.957 35.784 20.819 ;
     RECT  28.368 19.909 29.712 21.011 ;
     RECT  28.368 21.011 28.392 21.107 ;
     RECT  32.1 18.755 33.624 21.107 ;
     RECT  33.6 21.107 33.624 21.155 ;
     RECT  45.024 20.771 45.912 21.155 ;
     RECT  47.952 20.677 48.888 21.155 ;
     RECT  53.7 20.051 54.168 21.155 ;
     RECT  24 17.507 24.312 21.781 ;
     RECT  50.112 16.357 51.312 22.213 ;
     RECT  23.184 21.781 24.408 22.499 ;
     RECT  47.952 21.155 48.612 22.499 ;
     RECT  24 22.499 24.408 22.835 ;
     RECT  50.064 22.213 51.312 22.835 ;
     RECT  52.32 22.165 52.344 22.835 ;
     RECT  51 22.835 51.312 23.125 ;
     RECT  45.36 21.155 45.912 23.173 ;
     RECT  51 23.125 52.296 23.987 ;
     RECT  45.024 23.173 45.912 24.563 ;
     RECT  15.9 14.099 16.212 24.757 ;
     RECT  17.424 24.469 17.448 24.757 ;
     RECT  37.5 19.909 38.472 24.949 ;
     RECT  37.5 24.949 38.712 25.045 ;
     RECT  37.5 25.045 39.144 25.285 ;
     RECT  40.2 20.627 40.512 25.285 ;
     RECT  37.5 25.285 40.512 25.573 ;
     RECT  15.9 24.757 17.448 25.621 ;
     RECT  37.5 25.573 40.824 25.621 ;
     RECT  42.9 20.771 43.212 25.717 ;
     RECT  45.504 24.563 45.912 25.763 ;
     RECT  24 22.835 24.312 25.861 ;
     RECT  42.672 25.717 43.212 25.861 ;
     RECT  37.5 25.621 40.92 25.909 ;
     RECT  42.336 25.861 43.212 25.957 ;
     RECT  15.9 25.621 17.592 26.005 ;
     RECT  24 25.861 24.984 26.101 ;
     RECT  37.5 25.909 41.208 26.149 ;
     RECT  15.792 26.005 17.592 26.389 ;
     RECT  18.6 14.339 18.912 26.389 ;
     RECT  24 26.101 25.08 26.389 ;
     RECT  15.792 26.389 18.912 26.629 ;
     RECT  19.92 26.101 19.944 26.629 ;
     RECT  42.336 25.957 43.656 26.915 ;
     RECT  24 26.389 25.656 26.917 ;
     RECT  26.7 20.579 27.012 26.917 ;
     RECT  15.792 26.629 19.944 27.395 ;
     RECT  15.792 27.395 19.464 27.443 ;
     RECT  37.5 26.149 41.352 27.733 ;
     RECT  2.4 2.151 2.712 27.819 ;
     RECT  5.1 2.151 5.412 27.819 ;
     RECT  7.8 2.151 8.112 27.819 ;
     RECT  10.5 2.151 10.812 27.819 ;
     RECT  13.2 8.483 13.512 27.819 ;
     RECT  15.9 27.443 19.464 27.819 ;
     RECT  21.3 20.003 21.612 27.819 ;
     RECT  24 26.917 27.012 27.819 ;
     RECT  29.4 21.011 29.712 27.819 ;
     RECT  32.1 21.107 32.412 27.819 ;
     RECT  34.8 20.819 35.112 27.819 ;
     RECT  37.5 27.733 41.592 27.819 ;
     RECT  42.672 26.915 43.212 27.819 ;
     RECT  45.6 25.763 45.912 27.819 ;
     RECT  48.3 22.499 48.612 27.819 ;
     RECT  51 23.987 51.312 27.819 ;
     RECT  53.7 21.155 54.012 27.819 ;
     RECT  56.4 18.227 56.712 27.819 ;
     RECT  59.1 17.699 59.412 27.819 ;
     RECT  61.8 14.867 62.112 27.819 ;
     RECT  2.592 27.819 2.712 27.833 ;
     RECT  5.292 27.819 5.412 27.833 ;
     RECT  7.992 27.819 8.112 27.833 ;
     RECT  10.692 27.819 10.812 27.833 ;
     RECT  13.392 27.819 13.512 27.833 ;
     RECT  16.092 27.819 19.464 27.833 ;
     RECT  21.492 27.819 21.612 27.833 ;
     RECT  24.192 27.819 27.012 27.833 ;
     RECT  29.592 27.819 29.712 27.833 ;
     RECT  32.292 27.819 32.412 27.833 ;
     RECT  34.992 27.819 35.112 27.833 ;
     RECT  37.692 27.819 41.592 27.833 ;
     RECT  43.092 27.819 43.212 27.833 ;
     RECT  45.792 27.819 45.912 27.833 ;
     RECT  48.492 27.819 48.612 27.833 ;
     RECT  51.192 27.819 51.312 27.833 ;
     RECT  53.892 27.819 54.012 27.833 ;
     RECT  56.592 27.819 56.712 27.833 ;
     RECT  59.292 27.819 59.412 27.833 ;
     RECT  61.992 27.819 62.112 27.833 ;
     RECT  38.112 27.833 41.592 27.877 ;
     RECT  24.864 27.833 26.184 29.699 ;
     RECT  38.112 27.877 41.976 29.699 ;
     RECT  16.656 27.833 19.464 29.701 ;
     RECT  24.96 29.699 26.184 29.795 ;
     RECT  38.256 29.699 41.976 29.843 ;
     RECT  38.448 29.843 41.976 30.083 ;
     RECT  24.96 29.795 25.56 30.131 ;
     RECT  38.448 30.083 39.816 30.131 ;
     RECT  16.464 29.701 19.464 30.16 ;
     RECT  24.96 30.131 25.464 30.179 ;
     RECT  38.448 30.131 39.672 30.179 ;
     RECT  40.8 30.083 41.976 30.179 ;
  END
END qfd_landh0_128_NS_65x30
END LIBRARY
